# OT const_rename 128: packed / narrowed buses renamed (physical/die_plan/s81/inputs/const_pins_dropped.json)
VERSION 5.8 ;
BUSBITCHARS "[]" ;
DIVIDERCHAR "/" ;
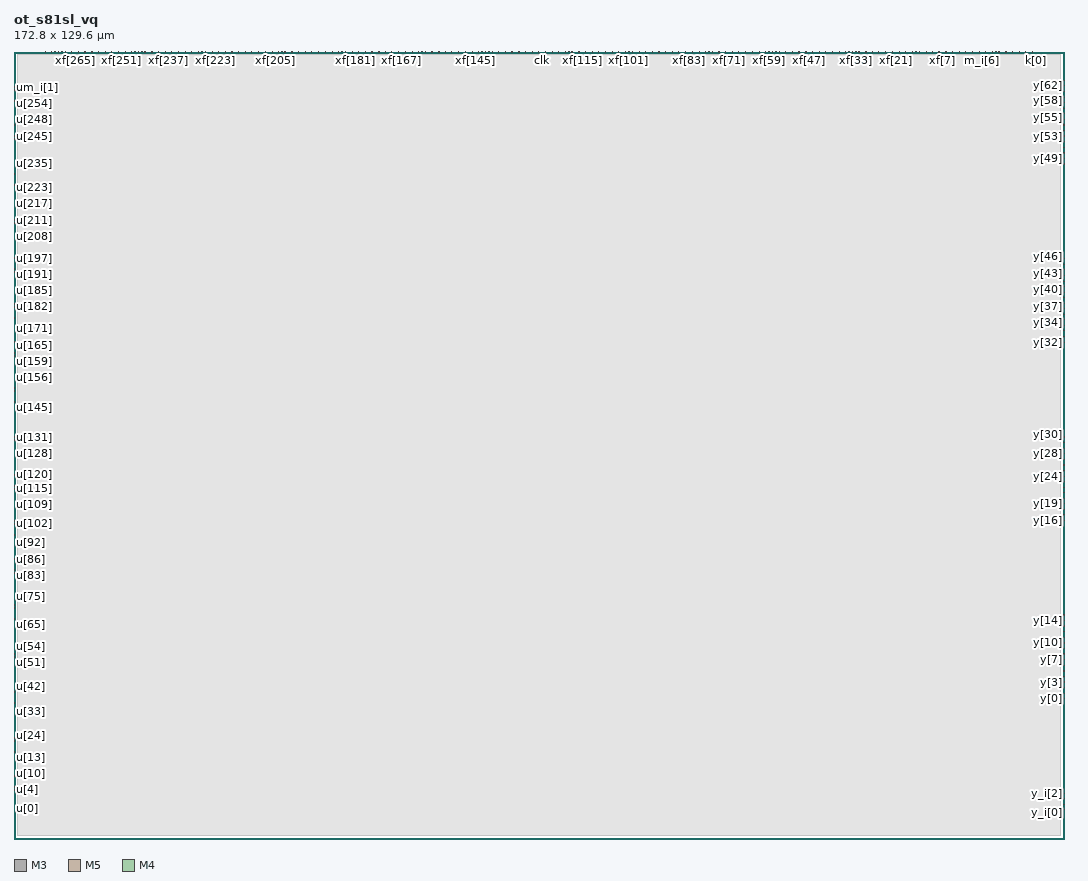
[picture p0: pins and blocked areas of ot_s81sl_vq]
MACRO ot_s81sl_vq
  CLASS BLOCK ;
  ORIGIN 0 0 ;
  FOREIGN ot_s81sl_vq 0 0 ;
  SIZE 172.800 BY 129.600 ;
  SYMMETRY X Y ;
  PIN clk
    DIRECTION INPUT ;
    USE SIGNAL ;
    PORT
      LAYER M3 ;
        RECT 86.9400 129.5620 86.9580 129.6000 ;
    END
  END clk
  PIN fault
    DIRECTION OUTPUT ;
    USE SIGNAL ;
    PORT
      LAYER M3 ;
        RECT 158.2920 129.5620 158.3100 129.6000 ;
    END
  END fault
  PIN k[0]
    DIRECTION INPUT ;
    USE SIGNAL ;
    PORT
      LAYER M3 ;
        RECT 168.1560 129.5620 168.1740 129.6000 ;
    END
  END k[0]
  PIN k[1]
    DIRECTION INPUT ;
    USE SIGNAL ;
    PORT
      LAYER M5 ;
        RECT 167.6640 129.5160 167.6880 129.6000 ;
    END
  END k[1]
  PIN k[2]
    DIRECTION INPUT ;
    USE SIGNAL ;
    PORT
      LAYER M3 ;
        RECT 167.0760 129.5620 167.0940 129.6000 ;
    END
  END k[2]
  PIN m_b
    DIRECTION INPUT ;
    USE SIGNAL ;
    PORT
      LAYER M5 ;
        RECT 163.2480 129.5160 163.2720 129.6000 ;
    END
  END m_b
  PIN m_i[0]
    DIRECTION INPUT ;
    USE SIGNAL ;
    PORT
      LAYER M3 ;
        RECT 162.6840 129.5620 162.7020 129.6000 ;
    END
  END m_i[0]
  PIN m_i[1]
    DIRECTION INPUT ;
    USE SIGNAL ;
    PORT
      LAYER M5 ;
        RECT 162.0960 129.5160 162.1200 129.6000 ;
    END
  END m_i[1]
  PIN m_i[2]
    DIRECTION INPUT ;
    USE SIGNAL ;
    PORT
      LAYER M3 ;
        RECT 161.6040 129.5620 161.6220 129.6000 ;
    END
  END m_i[2]
  PIN m_i[3]
    DIRECTION INPUT ;
    USE SIGNAL ;
    PORT
      LAYER M5 ;
        RECT 161.0400 129.5160 161.0640 129.6000 ;
    END
  END m_i[3]
  PIN m_i[4]
    DIRECTION INPUT ;
    USE SIGNAL ;
    PORT
      LAYER M3 ;
        RECT 160.5240 129.5620 160.5420 129.6000 ;
    END
  END m_i[4]
  PIN m_i[5]
    DIRECTION INPUT ;
    USE SIGNAL ;
    PORT
      LAYER M5 ;
        RECT 159.8880 129.5160 159.9120 129.6000 ;
    END
  END m_i[5]
  PIN m_i[6]
    DIRECTION INPUT ;
    USE SIGNAL ;
    PORT
      LAYER M3 ;
        RECT 159.3720 129.5620 159.3900 129.6000 ;
    END
  END m_i[6]
  PIN m_i[7]
    DIRECTION INPUT ;
    USE SIGNAL ;
    PORT
      LAYER M5 ;
        RECT 158.8320 129.5160 158.8560 129.6000 ;
    END
  END m_i[7]
  PIN m_q
    DIRECTION INPUT ;
    USE SIGNAL ;
    PORT
      LAYER M3 ;
        RECT 163.7640 129.5620 163.7820 129.6000 ;
    END
  END m_q
  PIN m_v
    DIRECTION INPUT ;
    USE SIGNAL ;
    PORT
      LAYER M5 ;
        RECT 164.3040 129.5160 164.3280 129.6000 ;
    END
  END m_v
  PIN rst_n
    DIRECTION INPUT ;
    USE SIGNAL ;
    PORT
      LAYER M5 ;
        RECT 86.3520 129.5160 86.3760 129.6000 ;
    END
  END rst_n
  PIN sid[0]
    DIRECTION INPUT ;
    USE SIGNAL ;
    PORT
      LAYER M5 ;
        RECT 166.5120 129.5160 166.5360 129.6000 ;
    END
  END sid[0]
  PIN sid[1]
    DIRECTION INPUT ;
    USE SIGNAL ;
    PORT
      LAYER M3 ;
        RECT 165.9960 129.5620 166.0140 129.6000 ;
    END
  END sid[1]
  PIN sid[2]
    DIRECTION INPUT ;
    USE SIGNAL ;
    PORT
      LAYER M5 ;
        RECT 165.4560 129.5160 165.4800 129.6000 ;
    END
  END sid[2]
  PIN sid[3]
    DIRECTION INPUT ;
    USE SIGNAL ;
    PORT
      LAYER M3 ;
        RECT 164.9160 129.5620 164.9340 129.6000 ;
    END
  END sid[3]
  PIN u[0]
    DIRECTION INPUT ;
    USE SIGNAL ;
    PORT
      LAYER M4 ;
        RECT 0.0000 6.3360 0.0840 6.3600 ;
    END
  END u[0]
  PIN u[100]
    DIRECTION INPUT ;
    USE SIGNAL ;
    PORT
      LAYER M4 ;
        RECT 0.0000 50.9760 0.0840 51.0000 ;
    END
  END u[100]
  PIN u[101]
    DIRECTION INPUT ;
    USE SIGNAL ;
    PORT
      LAYER M4 ;
        RECT 0.0000 51.3600 0.0840 51.3840 ;
    END
  END u[101]
  PIN u[102]
    DIRECTION INPUT ;
    USE SIGNAL ;
    PORT
      LAYER M4 ;
        RECT 0.0000 51.8400 0.0840 51.8640 ;
    END
  END u[102]
  PIN u[103]
    DIRECTION INPUT ;
    USE SIGNAL ;
    PORT
      LAYER M4 ;
        RECT 0.0000 52.3200 0.0840 52.3440 ;
    END
  END u[103]
  PIN u[104]
    DIRECTION INPUT ;
    USE SIGNAL ;
    PORT
      LAYER M4 ;
        RECT 0.0000 52.7040 0.0840 52.7280 ;
    END
  END u[104]
  PIN u[105]
    DIRECTION INPUT ;
    USE SIGNAL ;
    PORT
      LAYER M4 ;
        RECT 0.0000 53.1840 0.0840 53.2080 ;
    END
  END u[105]
  PIN u[106]
    DIRECTION INPUT ;
    USE SIGNAL ;
    PORT
      LAYER M4 ;
        RECT 0.0000 53.6640 0.0840 53.6880 ;
    END
  END u[106]
  PIN u[107]
    DIRECTION INPUT ;
    USE SIGNAL ;
    PORT
      LAYER M4 ;
        RECT 0.0000 54.0480 0.0840 54.0720 ;
    END
  END u[107]
  PIN u[108]
    DIRECTION INPUT ;
    USE SIGNAL ;
    PORT
      LAYER M4 ;
        RECT 0.0000 54.5280 0.0840 54.5520 ;
    END
  END u[108]
  PIN u[109]
    DIRECTION INPUT ;
    USE SIGNAL ;
    PORT
      LAYER M4 ;
        RECT 0.0000 55.0080 0.0840 55.0320 ;
    END
  END u[109]
  PIN u[10]
    DIRECTION INPUT ;
    USE SIGNAL ;
    PORT
      LAYER M4 ;
        RECT 0.0000 10.7520 0.0840 10.7760 ;
    END
  END u[10]
  PIN u[110]
    DIRECTION INPUT ;
    USE SIGNAL ;
    PORT
      LAYER M4 ;
        RECT 0.0000 55.3920 0.0840 55.4160 ;
    END
  END u[110]
  PIN u[111]
    DIRECTION INPUT ;
    USE SIGNAL ;
    PORT
      LAYER M4 ;
        RECT 0.0000 55.8720 0.0840 55.8960 ;
    END
  END u[111]
  PIN u[112]
    DIRECTION INPUT ;
    USE SIGNAL ;
    PORT
      LAYER M4 ;
        RECT 0.0000 56.3520 0.0840 56.3760 ;
    END
  END u[112]
  PIN u[113]
    DIRECTION INPUT ;
    USE SIGNAL ;
    PORT
      LAYER M4 ;
        RECT 0.0000 56.7360 0.0840 56.7600 ;
    END
  END u[113]
  PIN u[114]
    DIRECTION INPUT ;
    USE SIGNAL ;
    PORT
      LAYER M4 ;
        RECT 0.0000 57.2160 0.0840 57.2400 ;
    END
  END u[114]
  PIN u[115]
    DIRECTION INPUT ;
    USE SIGNAL ;
    PORT
      LAYER M4 ;
        RECT 0.0000 57.6000 0.0840 57.6240 ;
    END
  END u[115]
  PIN u[116]
    DIRECTION INPUT ;
    USE SIGNAL ;
    PORT
      LAYER M4 ;
        RECT 0.0000 58.0800 0.0840 58.1040 ;
    END
  END u[116]
  PIN u[117]
    DIRECTION INPUT ;
    USE SIGNAL ;
    PORT
      LAYER M4 ;
        RECT 0.0000 58.5600 0.0840 58.5840 ;
    END
  END u[117]
  PIN u[118]
    DIRECTION INPUT ;
    USE SIGNAL ;
    PORT
      LAYER M4 ;
        RECT 0.0000 58.9440 0.0840 58.9680 ;
    END
  END u[118]
  PIN u[119]
    DIRECTION INPUT ;
    USE SIGNAL ;
    PORT
      LAYER M4 ;
        RECT 0.0000 59.4240 0.0840 59.4480 ;
    END
  END u[119]
  PIN u[11]
    DIRECTION INPUT ;
    USE SIGNAL ;
    PORT
      LAYER M4 ;
        RECT 0.0000 11.2320 0.0840 11.2560 ;
    END
  END u[11]
  PIN u[120]
    DIRECTION INPUT ;
    USE SIGNAL ;
    PORT
      LAYER M4 ;
        RECT 0.0000 59.9040 0.0840 59.9280 ;
    END
  END u[120]
  PIN u[121]
    DIRECTION INPUT ;
    USE SIGNAL ;
    PORT
      LAYER M4 ;
        RECT 0.0000 60.2880 0.0840 60.3120 ;
    END
  END u[121]
  PIN u[122]
    DIRECTION INPUT ;
    USE SIGNAL ;
    PORT
      LAYER M4 ;
        RECT 0.0000 60.7680 0.0840 60.7920 ;
    END
  END u[122]
  PIN u[123]
    DIRECTION INPUT ;
    USE SIGNAL ;
    PORT
      LAYER M4 ;
        RECT 0.0000 61.2480 0.0840 61.2720 ;
    END
  END u[123]
  PIN u[124]
    DIRECTION INPUT ;
    USE SIGNAL ;
    PORT
      LAYER M4 ;
        RECT 0.0000 61.6320 0.0840 61.6560 ;
    END
  END u[124]
  PIN u[125]
    DIRECTION INPUT ;
    USE SIGNAL ;
    PORT
      LAYER M4 ;
        RECT 0.0000 62.1120 0.0840 62.1360 ;
    END
  END u[125]
  PIN u[126]
    DIRECTION INPUT ;
    USE SIGNAL ;
    PORT
      LAYER M4 ;
        RECT 0.0000 62.5920 0.0840 62.6160 ;
    END
  END u[126]
  PIN u[127]
    DIRECTION INPUT ;
    USE SIGNAL ;
    PORT
      LAYER M4 ;
        RECT 0.0000 62.9760 0.0840 63.0000 ;
    END
  END u[127]
  PIN u[128]
    DIRECTION INPUT ;
    USE SIGNAL ;
    PORT
      LAYER M4 ;
        RECT 0.0000 63.4560 0.0840 63.4800 ;
    END
  END u[128]
  PIN u[129]
    DIRECTION INPUT ;
    USE SIGNAL ;
    PORT
      LAYER M4 ;
        RECT 0.0000 63.9360 0.0840 63.9600 ;
    END
  END u[129]
  PIN u[12]
    DIRECTION INPUT ;
    USE SIGNAL ;
    PORT
      LAYER M4 ;
        RECT 0.0000 11.7120 0.0840 11.7360 ;
    END
  END u[12]
  PIN u[130]
    DIRECTION INPUT ;
    USE SIGNAL ;
    PORT
      LAYER M4 ;
        RECT 0.0000 64.3200 0.0840 64.3440 ;
    END
  END u[130]
  PIN u[131]
    DIRECTION INPUT ;
    USE SIGNAL ;
    PORT
      LAYER M4 ;
        RECT 0.0000 64.8000 0.0840 64.8240 ;
    END
  END u[131]
  PIN u[132]
    DIRECTION INPUT ;
    USE SIGNAL ;
    PORT
      LAYER M4 ;
        RECT 0.0000 65.2800 0.0840 65.3040 ;
    END
  END u[132]
  PIN u[133]
    DIRECTION INPUT ;
    USE SIGNAL ;
    PORT
      LAYER M4 ;
        RECT 0.0000 65.6640 0.0840 65.6880 ;
    END
  END u[133]
  PIN u[134]
    DIRECTION INPUT ;
    USE SIGNAL ;
    PORT
      LAYER M4 ;
        RECT 0.0000 66.1440 0.0840 66.1680 ;
    END
  END u[134]
  PIN u[135]
    DIRECTION INPUT ;
    USE SIGNAL ;
    PORT
      LAYER M4 ;
        RECT 0.0000 66.5280 0.0840 66.5520 ;
    END
  END u[135]
  PIN u[136]
    DIRECTION INPUT ;
    USE SIGNAL ;
    PORT
      LAYER M4 ;
        RECT 0.0000 67.0080 0.0840 67.0320 ;
    END
  END u[136]
  PIN u[137]
    DIRECTION INPUT ;
    USE SIGNAL ;
    PORT
      LAYER M4 ;
        RECT 0.0000 67.4880 0.0840 67.5120 ;
    END
  END u[137]
  PIN u[138]
    DIRECTION INPUT ;
    USE SIGNAL ;
    PORT
      LAYER M4 ;
        RECT 0.0000 67.8720 0.0840 67.8960 ;
    END
  END u[138]
  PIN u[139]
    DIRECTION INPUT ;
    USE SIGNAL ;
    PORT
      LAYER M4 ;
        RECT 0.0000 68.3520 0.0840 68.3760 ;
    END
  END u[139]
  PIN u[13]
    DIRECTION INPUT ;
    USE SIGNAL ;
    PORT
      LAYER M4 ;
        RECT 0.0000 12.0960 0.0840 12.1200 ;
    END
  END u[13]
  PIN u[140]
    DIRECTION INPUT ;
    USE SIGNAL ;
    PORT
      LAYER M4 ;
        RECT 0.0000 68.8320 0.0840 68.8560 ;
    END
  END u[140]
  PIN u[141]
    DIRECTION INPUT ;
    USE SIGNAL ;
    PORT
      LAYER M4 ;
        RECT 0.0000 69.2160 0.0840 69.2400 ;
    END
  END u[141]
  PIN u[142]
    DIRECTION INPUT ;
    USE SIGNAL ;
    PORT
      LAYER M4 ;
        RECT 0.0000 69.6960 0.0840 69.7200 ;
    END
  END u[142]
  PIN u[143]
    DIRECTION INPUT ;
    USE SIGNAL ;
    PORT
      LAYER M4 ;
        RECT 0.0000 70.1760 0.0840 70.2000 ;
    END
  END u[143]
  PIN u[144]
    DIRECTION INPUT ;
    USE SIGNAL ;
    PORT
      LAYER M4 ;
        RECT 0.0000 70.5600 0.0840 70.5840 ;
    END
  END u[144]
  PIN u[145]
    DIRECTION INPUT ;
    USE SIGNAL ;
    PORT
      LAYER M4 ;
        RECT 0.0000 71.0400 0.0840 71.0640 ;
    END
  END u[145]
  PIN u[146]
    DIRECTION INPUT ;
    USE SIGNAL ;
    PORT
      LAYER M4 ;
        RECT 0.0000 71.5200 0.0840 71.5440 ;
    END
  END u[146]
  PIN u[147]
    DIRECTION INPUT ;
    USE SIGNAL ;
    PORT
      LAYER M4 ;
        RECT 0.0000 71.9040 0.0840 71.9280 ;
    END
  END u[147]
  PIN u[148]
    DIRECTION INPUT ;
    USE SIGNAL ;
    PORT
      LAYER M4 ;
        RECT 0.0000 72.3840 0.0840 72.4080 ;
    END
  END u[148]
  PIN u[149]
    DIRECTION INPUT ;
    USE SIGNAL ;
    PORT
      LAYER M4 ;
        RECT 0.0000 72.8640 0.0840 72.8880 ;
    END
  END u[149]
  PIN u[14]
    DIRECTION INPUT ;
    USE SIGNAL ;
    PORT
      LAYER M4 ;
        RECT 0.0000 12.5760 0.0840 12.6000 ;
    END
  END u[14]
  PIN u[150]
    DIRECTION INPUT ;
    USE SIGNAL ;
    PORT
      LAYER M4 ;
        RECT 0.0000 73.2480 0.0840 73.2720 ;
    END
  END u[150]
  PIN u[151]
    DIRECTION INPUT ;
    USE SIGNAL ;
    PORT
      LAYER M4 ;
        RECT 0.0000 73.7280 0.0840 73.7520 ;
    END
  END u[151]
  PIN u[152]
    DIRECTION INPUT ;
    USE SIGNAL ;
    PORT
      LAYER M4 ;
        RECT 0.0000 74.2080 0.0840 74.2320 ;
    END
  END u[152]
  PIN u[153]
    DIRECTION INPUT ;
    USE SIGNAL ;
    PORT
      LAYER M4 ;
        RECT 0.0000 74.5920 0.0840 74.6160 ;
    END
  END u[153]
  PIN u[154]
    DIRECTION INPUT ;
    USE SIGNAL ;
    PORT
      LAYER M4 ;
        RECT 0.0000 75.0720 0.0840 75.0960 ;
    END
  END u[154]
  PIN u[155]
    DIRECTION INPUT ;
    USE SIGNAL ;
    PORT
      LAYER M4 ;
        RECT 0.0000 75.4560 0.0840 75.4800 ;
    END
  END u[155]
  PIN u[156]
    DIRECTION INPUT ;
    USE SIGNAL ;
    PORT
      LAYER M4 ;
        RECT 0.0000 75.9360 0.0840 75.9600 ;
    END
  END u[156]
  PIN u[157]
    DIRECTION INPUT ;
    USE SIGNAL ;
    PORT
      LAYER M4 ;
        RECT 0.0000 76.4160 0.0840 76.4400 ;
    END
  END u[157]
  PIN u[158]
    DIRECTION INPUT ;
    USE SIGNAL ;
    PORT
      LAYER M4 ;
        RECT 0.0000 76.8000 0.0840 76.8240 ;
    END
  END u[158]
  PIN u[159]
    DIRECTION INPUT ;
    USE SIGNAL ;
    PORT
      LAYER M4 ;
        RECT 0.0000 77.2800 0.0840 77.3040 ;
    END
  END u[159]
  PIN u[15]
    DIRECTION INPUT ;
    USE SIGNAL ;
    PORT
      LAYER M4 ;
        RECT 0.0000 13.0560 0.0840 13.0800 ;
    END
  END u[15]
  PIN u[160]
    DIRECTION INPUT ;
    USE SIGNAL ;
    PORT
      LAYER M4 ;
        RECT 0.0000 77.7600 0.0840 77.7840 ;
    END
  END u[160]
  PIN u[161]
    DIRECTION INPUT ;
    USE SIGNAL ;
    PORT
      LAYER M4 ;
        RECT 0.0000 78.1440 0.0840 78.1680 ;
    END
  END u[161]
  PIN u[162]
    DIRECTION INPUT ;
    USE SIGNAL ;
    PORT
      LAYER M4 ;
        RECT 0.0000 78.6240 0.0840 78.6480 ;
    END
  END u[162]
  PIN u[163]
    DIRECTION INPUT ;
    USE SIGNAL ;
    PORT
      LAYER M4 ;
        RECT 0.0000 79.1040 0.0840 79.1280 ;
    END
  END u[163]
  PIN u[164]
    DIRECTION INPUT ;
    USE SIGNAL ;
    PORT
      LAYER M4 ;
        RECT 0.0000 79.4880 0.0840 79.5120 ;
    END
  END u[164]
  PIN u[165]
    DIRECTION INPUT ;
    USE SIGNAL ;
    PORT
      LAYER M4 ;
        RECT 0.0000 79.9680 0.0840 79.9920 ;
    END
  END u[165]
  PIN u[166]
    DIRECTION INPUT ;
    USE SIGNAL ;
    PORT
      LAYER M4 ;
        RECT 0.0000 80.4480 0.0840 80.4720 ;
    END
  END u[166]
  PIN u[167]
    DIRECTION INPUT ;
    USE SIGNAL ;
    PORT
      LAYER M4 ;
        RECT 0.0000 80.8320 0.0840 80.8560 ;
    END
  END u[167]
  PIN u[168]
    DIRECTION INPUT ;
    USE SIGNAL ;
    PORT
      LAYER M4 ;
        RECT 0.0000 81.3120 0.0840 81.3360 ;
    END
  END u[168]
  PIN u[169]
    DIRECTION INPUT ;
    USE SIGNAL ;
    PORT
      LAYER M4 ;
        RECT 0.0000 81.7920 0.0840 81.8160 ;
    END
  END u[169]
  PIN u[16]
    DIRECTION INPUT ;
    USE SIGNAL ;
    PORT
      LAYER M4 ;
        RECT 0.0000 13.4400 0.0840 13.4640 ;
    END
  END u[16]
  PIN u[170]
    DIRECTION INPUT ;
    USE SIGNAL ;
    PORT
      LAYER M4 ;
        RECT 0.0000 82.1760 0.0840 82.2000 ;
    END
  END u[170]
  PIN u[171]
    DIRECTION INPUT ;
    USE SIGNAL ;
    PORT
      LAYER M4 ;
        RECT 0.0000 82.6560 0.0840 82.6800 ;
    END
  END u[171]
  PIN u[172]
    DIRECTION INPUT ;
    USE SIGNAL ;
    PORT
      LAYER M4 ;
        RECT 0.0000 83.1360 0.0840 83.1600 ;
    END
  END u[172]
  PIN u[173]
    DIRECTION INPUT ;
    USE SIGNAL ;
    PORT
      LAYER M4 ;
        RECT 0.0000 83.5200 0.0840 83.5440 ;
    END
  END u[173]
  PIN u[174]
    DIRECTION INPUT ;
    USE SIGNAL ;
    PORT
      LAYER M4 ;
        RECT 0.0000 84.0000 0.0840 84.0240 ;
    END
  END u[174]
  PIN u[175]
    DIRECTION INPUT ;
    USE SIGNAL ;
    PORT
      LAYER M4 ;
        RECT 0.0000 84.3840 0.0840 84.4080 ;
    END
  END u[175]
  PIN u[176]
    DIRECTION INPUT ;
    USE SIGNAL ;
    PORT
      LAYER M4 ;
        RECT 0.0000 84.8640 0.0840 84.8880 ;
    END
  END u[176]
  PIN u[177]
    DIRECTION INPUT ;
    USE SIGNAL ;
    PORT
      LAYER M4 ;
        RECT 0.0000 85.3440 0.0840 85.3680 ;
    END
  END u[177]
  PIN u[178]
    DIRECTION INPUT ;
    USE SIGNAL ;
    PORT
      LAYER M4 ;
        RECT 0.0000 85.7280 0.0840 85.7520 ;
    END
  END u[178]
  PIN u[179]
    DIRECTION INPUT ;
    USE SIGNAL ;
    PORT
      LAYER M4 ;
        RECT 0.0000 86.2080 0.0840 86.2320 ;
    END
  END u[179]
  PIN u[17]
    DIRECTION INPUT ;
    USE SIGNAL ;
    PORT
      LAYER M4 ;
        RECT 0.0000 13.9200 0.0840 13.9440 ;
    END
  END u[17]
  PIN u[180]
    DIRECTION INPUT ;
    USE SIGNAL ;
    PORT
      LAYER M4 ;
        RECT 0.0000 86.6880 0.0840 86.7120 ;
    END
  END u[180]
  PIN u[181]
    DIRECTION INPUT ;
    USE SIGNAL ;
    PORT
      LAYER M4 ;
        RECT 0.0000 87.0720 0.0840 87.0960 ;
    END
  END u[181]
  PIN u[182]
    DIRECTION INPUT ;
    USE SIGNAL ;
    PORT
      LAYER M4 ;
        RECT 0.0000 87.5520 0.0840 87.5760 ;
    END
  END u[182]
  PIN u[183]
    DIRECTION INPUT ;
    USE SIGNAL ;
    PORT
      LAYER M4 ;
        RECT 0.0000 88.0320 0.0840 88.0560 ;
    END
  END u[183]
  PIN u[184]
    DIRECTION INPUT ;
    USE SIGNAL ;
    PORT
      LAYER M4 ;
        RECT 0.0000 88.4160 0.0840 88.4400 ;
    END
  END u[184]
  PIN u[185]
    DIRECTION INPUT ;
    USE SIGNAL ;
    PORT
      LAYER M4 ;
        RECT 0.0000 88.8960 0.0840 88.9200 ;
    END
  END u[185]
  PIN u[186]
    DIRECTION INPUT ;
    USE SIGNAL ;
    PORT
      LAYER M4 ;
        RECT 0.0000 89.3760 0.0840 89.4000 ;
    END
  END u[186]
  PIN u[187]
    DIRECTION INPUT ;
    USE SIGNAL ;
    PORT
      LAYER M4 ;
        RECT 0.0000 89.7600 0.0840 89.7840 ;
    END
  END u[187]
  PIN u[188]
    DIRECTION INPUT ;
    USE SIGNAL ;
    PORT
      LAYER M4 ;
        RECT 0.0000 90.2400 0.0840 90.2640 ;
    END
  END u[188]
  PIN u[189]
    DIRECTION INPUT ;
    USE SIGNAL ;
    PORT
      LAYER M4 ;
        RECT 0.0000 90.7200 0.0840 90.7440 ;
    END
  END u[189]
  PIN u[18]
    DIRECTION INPUT ;
    USE SIGNAL ;
    PORT
      LAYER M4 ;
        RECT 0.0000 14.3040 0.0840 14.3280 ;
    END
  END u[18]
  PIN u[190]
    DIRECTION INPUT ;
    USE SIGNAL ;
    PORT
      LAYER M4 ;
        RECT 0.0000 91.1040 0.0840 91.1280 ;
    END
  END u[190]
  PIN u[191]
    DIRECTION INPUT ;
    USE SIGNAL ;
    PORT
      LAYER M4 ;
        RECT 0.0000 91.5840 0.0840 91.6080 ;
    END
  END u[191]
  PIN u[192]
    DIRECTION INPUT ;
    USE SIGNAL ;
    PORT
      LAYER M4 ;
        RECT 0.0000 91.9680 0.0840 91.9920 ;
    END
  END u[192]
  PIN u[193]
    DIRECTION INPUT ;
    USE SIGNAL ;
    PORT
      LAYER M4 ;
        RECT 0.0000 92.4480 0.0840 92.4720 ;
    END
  END u[193]
  PIN u[194]
    DIRECTION INPUT ;
    USE SIGNAL ;
    PORT
      LAYER M4 ;
        RECT 0.0000 92.9280 0.0840 92.9520 ;
    END
  END u[194]
  PIN u[195]
    DIRECTION INPUT ;
    USE SIGNAL ;
    PORT
      LAYER M4 ;
        RECT 0.0000 93.3120 0.0840 93.3360 ;
    END
  END u[195]
  PIN u[196]
    DIRECTION INPUT ;
    USE SIGNAL ;
    PORT
      LAYER M4 ;
        RECT 0.0000 93.7920 0.0840 93.8160 ;
    END
  END u[196]
  PIN u[197]
    DIRECTION INPUT ;
    USE SIGNAL ;
    PORT
      LAYER M4 ;
        RECT 0.0000 94.2720 0.0840 94.2960 ;
    END
  END u[197]
  PIN u[198]
    DIRECTION INPUT ;
    USE SIGNAL ;
    PORT
      LAYER M4 ;
        RECT 0.0000 94.6560 0.0840 94.6800 ;
    END
  END u[198]
  PIN u[199]
    DIRECTION INPUT ;
    USE SIGNAL ;
    PORT
      LAYER M4 ;
        RECT 0.0000 95.1360 0.0840 95.1600 ;
    END
  END u[199]
  PIN u[19]
    DIRECTION INPUT ;
    USE SIGNAL ;
    PORT
      LAYER M4 ;
        RECT 0.0000 14.7840 0.0840 14.8080 ;
    END
  END u[19]
  PIN u[1]
    DIRECTION INPUT ;
    USE SIGNAL ;
    PORT
      LAYER M4 ;
        RECT 0.0000 6.7200 0.0840 6.7440 ;
    END
  END u[1]
  PIN u[200]
    DIRECTION INPUT ;
    USE SIGNAL ;
    PORT
      LAYER M4 ;
        RECT 0.0000 95.6160 0.0840 95.6400 ;
    END
  END u[200]
  PIN u[201]
    DIRECTION INPUT ;
    USE SIGNAL ;
    PORT
      LAYER M4 ;
        RECT 0.0000 96.0000 0.0840 96.0240 ;
    END
  END u[201]
  PIN u[202]
    DIRECTION INPUT ;
    USE SIGNAL ;
    PORT
      LAYER M4 ;
        RECT 0.0000 96.4800 0.0840 96.5040 ;
    END
  END u[202]
  PIN u[203]
    DIRECTION INPUT ;
    USE SIGNAL ;
    PORT
      LAYER M4 ;
        RECT 0.0000 96.9600 0.0840 96.9840 ;
    END
  END u[203]
  PIN u[204]
    DIRECTION INPUT ;
    USE SIGNAL ;
    PORT
      LAYER M4 ;
        RECT 0.0000 97.3440 0.0840 97.3680 ;
    END
  END u[204]
  PIN u[205]
    DIRECTION INPUT ;
    USE SIGNAL ;
    PORT
      LAYER M4 ;
        RECT 0.0000 97.8240 0.0840 97.8480 ;
    END
  END u[205]
  PIN u[206]
    DIRECTION INPUT ;
    USE SIGNAL ;
    PORT
      LAYER M4 ;
        RECT 0.0000 98.3040 0.0840 98.3280 ;
    END
  END u[206]
  PIN u[207]
    DIRECTION INPUT ;
    USE SIGNAL ;
    PORT
      LAYER M4 ;
        RECT 0.0000 98.6880 0.0840 98.7120 ;
    END
  END u[207]
  PIN u[208]
    DIRECTION INPUT ;
    USE SIGNAL ;
    PORT
      LAYER M4 ;
        RECT 0.0000 99.1680 0.0840 99.1920 ;
    END
  END u[208]
  PIN u[209]
    DIRECTION INPUT ;
    USE SIGNAL ;
    PORT
      LAYER M4 ;
        RECT 0.0000 99.6480 0.0840 99.6720 ;
    END
  END u[209]
  PIN u[20]
    DIRECTION INPUT ;
    USE SIGNAL ;
    PORT
      LAYER M4 ;
        RECT 0.0000 15.2640 0.0840 15.2880 ;
    END
  END u[20]
  PIN u[210]
    DIRECTION INPUT ;
    USE SIGNAL ;
    PORT
      LAYER M4 ;
        RECT 0.0000 100.0320 0.0840 100.0560 ;
    END
  END u[210]
  PIN u[211]
    DIRECTION INPUT ;
    USE SIGNAL ;
    PORT
      LAYER M4 ;
        RECT 0.0000 100.5120 0.0840 100.5360 ;
    END
  END u[211]
  PIN u[212]
    DIRECTION INPUT ;
    USE SIGNAL ;
    PORT
      LAYER M4 ;
        RECT 0.0000 100.8960 0.0840 100.9200 ;
    END
  END u[212]
  PIN u[213]
    DIRECTION INPUT ;
    USE SIGNAL ;
    PORT
      LAYER M4 ;
        RECT 0.0000 101.3760 0.0840 101.4000 ;
    END
  END u[213]
  PIN u[214]
    DIRECTION INPUT ;
    USE SIGNAL ;
    PORT
      LAYER M4 ;
        RECT 0.0000 101.8560 0.0840 101.8800 ;
    END
  END u[214]
  PIN u[215]
    DIRECTION INPUT ;
    USE SIGNAL ;
    PORT
      LAYER M4 ;
        RECT 0.0000 102.2400 0.0840 102.2640 ;
    END
  END u[215]
  PIN u[216]
    DIRECTION INPUT ;
    USE SIGNAL ;
    PORT
      LAYER M4 ;
        RECT 0.0000 102.7200 0.0840 102.7440 ;
    END
  END u[216]
  PIN u[217]
    DIRECTION INPUT ;
    USE SIGNAL ;
    PORT
      LAYER M4 ;
        RECT 0.0000 103.2000 0.0840 103.2240 ;
    END
  END u[217]
  PIN u[218]
    DIRECTION INPUT ;
    USE SIGNAL ;
    PORT
      LAYER M4 ;
        RECT 0.0000 103.5840 0.0840 103.6080 ;
    END
  END u[218]
  PIN u[219]
    DIRECTION INPUT ;
    USE SIGNAL ;
    PORT
      LAYER M4 ;
        RECT 0.0000 104.0640 0.0840 104.0880 ;
    END
  END u[219]
  PIN u[21]
    DIRECTION INPUT ;
    USE SIGNAL ;
    PORT
      LAYER M4 ;
        RECT 0.0000 15.6480 0.0840 15.6720 ;
    END
  END u[21]
  PIN u[220]
    DIRECTION INPUT ;
    USE SIGNAL ;
    PORT
      LAYER M4 ;
        RECT 0.0000 104.5440 0.0840 104.5680 ;
    END
  END u[220]
  PIN u[221]
    DIRECTION INPUT ;
    USE SIGNAL ;
    PORT
      LAYER M4 ;
        RECT 0.0000 104.9280 0.0840 104.9520 ;
    END
  END u[221]
  PIN u[222]
    DIRECTION INPUT ;
    USE SIGNAL ;
    PORT
      LAYER M4 ;
        RECT 0.0000 105.4080 0.0840 105.4320 ;
    END
  END u[222]
  PIN u[223]
    DIRECTION INPUT ;
    USE SIGNAL ;
    PORT
      LAYER M4 ;
        RECT 0.0000 105.8880 0.0840 105.9120 ;
    END
  END u[223]
  PIN u[224]
    DIRECTION INPUT ;
    USE SIGNAL ;
    PORT
      LAYER M4 ;
        RECT 0.0000 106.2720 0.0840 106.2960 ;
    END
  END u[224]
  PIN u[225]
    DIRECTION INPUT ;
    USE SIGNAL ;
    PORT
      LAYER M4 ;
        RECT 0.0000 106.7520 0.0840 106.7760 ;
    END
  END u[225]
  PIN u[226]
    DIRECTION INPUT ;
    USE SIGNAL ;
    PORT
      LAYER M4 ;
        RECT 0.0000 107.2320 0.0840 107.2560 ;
    END
  END u[226]
  PIN u[227]
    DIRECTION INPUT ;
    USE SIGNAL ;
    PORT
      LAYER M4 ;
        RECT 0.0000 107.6160 0.0840 107.6400 ;
    END
  END u[227]
  PIN u[228]
    DIRECTION INPUT ;
    USE SIGNAL ;
    PORT
      LAYER M4 ;
        RECT 0.0000 108.0960 0.0840 108.1200 ;
    END
  END u[228]
  PIN u[229]
    DIRECTION INPUT ;
    USE SIGNAL ;
    PORT
      LAYER M4 ;
        RECT 0.0000 108.5760 0.0840 108.6000 ;
    END
  END u[229]
  PIN u[22]
    DIRECTION INPUT ;
    USE SIGNAL ;
    PORT
      LAYER M4 ;
        RECT 0.0000 16.1280 0.0840 16.1520 ;
    END
  END u[22]
  PIN u[230]
    DIRECTION INPUT ;
    USE SIGNAL ;
    PORT
      LAYER M4 ;
        RECT 0.0000 108.9600 0.0840 108.9840 ;
    END
  END u[230]
  PIN u[231]
    DIRECTION INPUT ;
    USE SIGNAL ;
    PORT
      LAYER M4 ;
        RECT 0.0000 109.4400 0.0840 109.4640 ;
    END
  END u[231]
  PIN u[232]
    DIRECTION INPUT ;
    USE SIGNAL ;
    PORT
      LAYER M4 ;
        RECT 0.0000 109.8240 0.0840 109.8480 ;
    END
  END u[232]
  PIN u[233]
    DIRECTION INPUT ;
    USE SIGNAL ;
    PORT
      LAYER M4 ;
        RECT 0.0000 110.3040 0.0840 110.3280 ;
    END
  END u[233]
  PIN u[234]
    DIRECTION INPUT ;
    USE SIGNAL ;
    PORT
      LAYER M4 ;
        RECT 0.0000 110.7840 0.0840 110.8080 ;
    END
  END u[234]
  PIN u[235]
    DIRECTION INPUT ;
    USE SIGNAL ;
    PORT
      LAYER M4 ;
        RECT 0.0000 111.1680 0.0840 111.1920 ;
    END
  END u[235]
  PIN u[236]
    DIRECTION INPUT ;
    USE SIGNAL ;
    PORT
      LAYER M4 ;
        RECT 0.0000 111.6480 0.0840 111.6720 ;
    END
  END u[236]
  PIN u[237]
    DIRECTION INPUT ;
    USE SIGNAL ;
    PORT
      LAYER M4 ;
        RECT 0.0000 112.1280 0.0840 112.1520 ;
    END
  END u[237]
  PIN u[238]
    DIRECTION INPUT ;
    USE SIGNAL ;
    PORT
      LAYER M4 ;
        RECT 0.0000 112.5120 0.0840 112.5360 ;
    END
  END u[238]
  PIN u[239]
    DIRECTION INPUT ;
    USE SIGNAL ;
    PORT
      LAYER M4 ;
        RECT 0.0000 112.9920 0.0840 113.0160 ;
    END
  END u[239]
  PIN u[23]
    DIRECTION INPUT ;
    USE SIGNAL ;
    PORT
      LAYER M4 ;
        RECT 0.0000 16.6080 0.0840 16.6320 ;
    END
  END u[23]
  PIN u[240]
    DIRECTION INPUT ;
    USE SIGNAL ;
    PORT
      LAYER M4 ;
        RECT 0.0000 113.4720 0.0840 113.4960 ;
    END
  END u[240]
  PIN u[241]
    DIRECTION INPUT ;
    USE SIGNAL ;
    PORT
      LAYER M4 ;
        RECT 0.0000 113.8560 0.0840 113.8800 ;
    END
  END u[241]
  PIN u[242]
    DIRECTION INPUT ;
    USE SIGNAL ;
    PORT
      LAYER M4 ;
        RECT 0.0000 114.3360 0.0840 114.3600 ;
    END
  END u[242]
  PIN u[243]
    DIRECTION INPUT ;
    USE SIGNAL ;
    PORT
      LAYER M4 ;
        RECT 0.0000 114.8160 0.0840 114.8400 ;
    END
  END u[243]
  PIN u[244]
    DIRECTION INPUT ;
    USE SIGNAL ;
    PORT
      LAYER M4 ;
        RECT 0.0000 115.2000 0.0840 115.2240 ;
    END
  END u[244]
  PIN u[245]
    DIRECTION INPUT ;
    USE SIGNAL ;
    PORT
      LAYER M4 ;
        RECT 0.0000 115.6800 0.0840 115.7040 ;
    END
  END u[245]
  PIN u[246]
    DIRECTION INPUT ;
    USE SIGNAL ;
    PORT
      LAYER M4 ;
        RECT 0.0000 116.1600 0.0840 116.1840 ;
    END
  END u[246]
  PIN u[247]
    DIRECTION INPUT ;
    USE SIGNAL ;
    PORT
      LAYER M4 ;
        RECT 0.0000 116.5440 0.0840 116.5680 ;
    END
  END u[247]
  PIN u[248]
    DIRECTION INPUT ;
    USE SIGNAL ;
    PORT
      LAYER M4 ;
        RECT 0.0000 117.0240 0.0840 117.0480 ;
    END
  END u[248]
  PIN u[249]
    DIRECTION INPUT ;
    USE SIGNAL ;
    PORT
      LAYER M4 ;
        RECT 0.0000 117.5040 0.0840 117.5280 ;
    END
  END u[249]
  PIN u[24]
    DIRECTION INPUT ;
    USE SIGNAL ;
    PORT
      LAYER M4 ;
        RECT 0.0000 16.9920 0.0840 17.0160 ;
    END
  END u[24]
  PIN u[250]
    DIRECTION INPUT ;
    USE SIGNAL ;
    PORT
      LAYER M4 ;
        RECT 0.0000 117.8880 0.0840 117.9120 ;
    END
  END u[250]
  PIN u[251]
    DIRECTION INPUT ;
    USE SIGNAL ;
    PORT
      LAYER M4 ;
        RECT 0.0000 118.3680 0.0840 118.3920 ;
    END
  END u[251]
  PIN u[252]
    DIRECTION INPUT ;
    USE SIGNAL ;
    PORT
      LAYER M4 ;
        RECT 0.0000 118.7520 0.0840 118.7760 ;
    END
  END u[252]
  PIN u[253]
    DIRECTION INPUT ;
    USE SIGNAL ;
    PORT
      LAYER M4 ;
        RECT 0.0000 119.2320 0.0840 119.2560 ;
    END
  END u[253]
  PIN u[254]
    DIRECTION INPUT ;
    USE SIGNAL ;
    PORT
      LAYER M4 ;
        RECT 0.0000 119.7120 0.0840 119.7360 ;
    END
  END u[254]
  PIN u[255]
    DIRECTION INPUT ;
    USE SIGNAL ;
    PORT
      LAYER M4 ;
        RECT 0.0000 120.0960 0.0840 120.1200 ;
    END
  END u[255]
  PIN u[25]
    DIRECTION INPUT ;
    USE SIGNAL ;
    PORT
      LAYER M4 ;
        RECT 0.0000 17.4720 0.0840 17.4960 ;
    END
  END u[25]
  PIN u[26]
    DIRECTION INPUT ;
    USE SIGNAL ;
    PORT
      LAYER M4 ;
        RECT 0.0000 17.9520 0.0840 17.9760 ;
    END
  END u[26]
  PIN u[27]
    DIRECTION INPUT ;
    USE SIGNAL ;
    PORT
      LAYER M4 ;
        RECT 0.0000 18.3360 0.0840 18.3600 ;
    END
  END u[27]
  PIN u[28]
    DIRECTION INPUT ;
    USE SIGNAL ;
    PORT
      LAYER M4 ;
        RECT 0.0000 18.8160 0.0840 18.8400 ;
    END
  END u[28]
  PIN u[29]
    DIRECTION INPUT ;
    USE SIGNAL ;
    PORT
      LAYER M4 ;
        RECT 0.0000 19.2960 0.0840 19.3200 ;
    END
  END u[29]
  PIN u[2]
    DIRECTION INPUT ;
    USE SIGNAL ;
    PORT
      LAYER M4 ;
        RECT 0.0000 7.2000 0.0840 7.2240 ;
    END
  END u[2]
  PIN u[30]
    DIRECTION INPUT ;
    USE SIGNAL ;
    PORT
      LAYER M4 ;
        RECT 0.0000 19.6800 0.0840 19.7040 ;
    END
  END u[30]
  PIN u[31]
    DIRECTION INPUT ;
    USE SIGNAL ;
    PORT
      LAYER M4 ;
        RECT 0.0000 20.1600 0.0840 20.1840 ;
    END
  END u[31]
  PIN u[32]
    DIRECTION INPUT ;
    USE SIGNAL ;
    PORT
      LAYER M4 ;
        RECT 0.0000 20.6400 0.0840 20.6640 ;
    END
  END u[32]
  PIN u[33]
    DIRECTION INPUT ;
    USE SIGNAL ;
    PORT
      LAYER M4 ;
        RECT 0.0000 21.0240 0.0840 21.0480 ;
    END
  END u[33]
  PIN u[34]
    DIRECTION INPUT ;
    USE SIGNAL ;
    PORT
      LAYER M4 ;
        RECT 0.0000 21.5040 0.0840 21.5280 ;
    END
  END u[34]
  PIN u[35]
    DIRECTION INPUT ;
    USE SIGNAL ;
    PORT
      LAYER M4 ;
        RECT 0.0000 21.9840 0.0840 22.0080 ;
    END
  END u[35]
  PIN u[36]
    DIRECTION INPUT ;
    USE SIGNAL ;
    PORT
      LAYER M4 ;
        RECT 0.0000 22.3680 0.0840 22.3920 ;
    END
  END u[36]
  PIN u[37]
    DIRECTION INPUT ;
    USE SIGNAL ;
    PORT
      LAYER M4 ;
        RECT 0.0000 22.8480 0.0840 22.8720 ;
    END
  END u[37]
  PIN u[38]
    DIRECTION INPUT ;
    USE SIGNAL ;
    PORT
      LAYER M4 ;
        RECT 0.0000 23.2320 0.0840 23.2560 ;
    END
  END u[38]
  PIN u[39]
    DIRECTION INPUT ;
    USE SIGNAL ;
    PORT
      LAYER M4 ;
        RECT 0.0000 23.7120 0.0840 23.7360 ;
    END
  END u[39]
  PIN u[3]
    DIRECTION INPUT ;
    USE SIGNAL ;
    PORT
      LAYER M4 ;
        RECT 0.0000 7.6800 0.0840 7.7040 ;
    END
  END u[3]
  PIN u[40]
    DIRECTION INPUT ;
    USE SIGNAL ;
    PORT
      LAYER M4 ;
        RECT 0.0000 24.1920 0.0840 24.2160 ;
    END
  END u[40]
  PIN u[41]
    DIRECTION INPUT ;
    USE SIGNAL ;
    PORT
      LAYER M4 ;
        RECT 0.0000 24.5760 0.0840 24.6000 ;
    END
  END u[41]
  PIN u[42]
    DIRECTION INPUT ;
    USE SIGNAL ;
    PORT
      LAYER M4 ;
        RECT 0.0000 25.0560 0.0840 25.0800 ;
    END
  END u[42]
  PIN u[43]
    DIRECTION INPUT ;
    USE SIGNAL ;
    PORT
      LAYER M4 ;
        RECT 0.0000 25.5360 0.0840 25.5600 ;
    END
  END u[43]
  PIN u[44]
    DIRECTION INPUT ;
    USE SIGNAL ;
    PORT
      LAYER M4 ;
        RECT 0.0000 25.9200 0.0840 25.9440 ;
    END
  END u[44]
  PIN u[45]
    DIRECTION INPUT ;
    USE SIGNAL ;
    PORT
      LAYER M4 ;
        RECT 0.0000 26.4000 0.0840 26.4240 ;
    END
  END u[45]
  PIN u[46]
    DIRECTION INPUT ;
    USE SIGNAL ;
    PORT
      LAYER M4 ;
        RECT 0.0000 26.8800 0.0840 26.9040 ;
    END
  END u[46]
  PIN u[47]
    DIRECTION INPUT ;
    USE SIGNAL ;
    PORT
      LAYER M4 ;
        RECT 0.0000 27.2640 0.0840 27.2880 ;
    END
  END u[47]
  PIN u[48]
    DIRECTION INPUT ;
    USE SIGNAL ;
    PORT
      LAYER M4 ;
        RECT 0.0000 27.7440 0.0840 27.7680 ;
    END
  END u[48]
  PIN u[49]
    DIRECTION INPUT ;
    USE SIGNAL ;
    PORT
      LAYER M4 ;
        RECT 0.0000 28.2240 0.0840 28.2480 ;
    END
  END u[49]
  PIN u[4]
    DIRECTION INPUT ;
    USE SIGNAL ;
    PORT
      LAYER M4 ;
        RECT 0.0000 8.0640 0.0840 8.0880 ;
    END
  END u[4]
  PIN u[50]
    DIRECTION INPUT ;
    USE SIGNAL ;
    PORT
      LAYER M4 ;
        RECT 0.0000 28.6080 0.0840 28.6320 ;
    END
  END u[50]
  PIN u[51]
    DIRECTION INPUT ;
    USE SIGNAL ;
    PORT
      LAYER M4 ;
        RECT 0.0000 29.0880 0.0840 29.1120 ;
    END
  END u[51]
  PIN u[52]
    DIRECTION INPUT ;
    USE SIGNAL ;
    PORT
      LAYER M4 ;
        RECT 0.0000 29.5680 0.0840 29.5920 ;
    END
  END u[52]
  PIN u[53]
    DIRECTION INPUT ;
    USE SIGNAL ;
    PORT
      LAYER M4 ;
        RECT 0.0000 29.9520 0.0840 29.9760 ;
    END
  END u[53]
  PIN u[54]
    DIRECTION INPUT ;
    USE SIGNAL ;
    PORT
      LAYER M4 ;
        RECT 0.0000 30.4320 0.0840 30.4560 ;
    END
  END u[54]
  PIN u[55]
    DIRECTION INPUT ;
    USE SIGNAL ;
    PORT
      LAYER M4 ;
        RECT 0.0000 30.9120 0.0840 30.9360 ;
    END
  END u[55]
  PIN u[56]
    DIRECTION INPUT ;
    USE SIGNAL ;
    PORT
      LAYER M4 ;
        RECT 0.0000 31.2960 0.0840 31.3200 ;
    END
  END u[56]
  PIN u[57]
    DIRECTION INPUT ;
    USE SIGNAL ;
    PORT
      LAYER M4 ;
        RECT 0.0000 31.7760 0.0840 31.8000 ;
    END
  END u[57]
  PIN u[58]
    DIRECTION INPUT ;
    USE SIGNAL ;
    PORT
      LAYER M4 ;
        RECT 0.0000 32.1600 0.0840 32.1840 ;
    END
  END u[58]
  PIN u[59]
    DIRECTION INPUT ;
    USE SIGNAL ;
    PORT
      LAYER M4 ;
        RECT 0.0000 32.6400 0.0840 32.6640 ;
    END
  END u[59]
  PIN u[5]
    DIRECTION INPUT ;
    USE SIGNAL ;
    PORT
      LAYER M4 ;
        RECT 0.0000 8.5440 0.0840 8.5680 ;
    END
  END u[5]
  PIN u[60]
    DIRECTION INPUT ;
    USE SIGNAL ;
    PORT
      LAYER M4 ;
        RECT 0.0000 33.1200 0.0840 33.1440 ;
    END
  END u[60]
  PIN u[61]
    DIRECTION INPUT ;
    USE SIGNAL ;
    PORT
      LAYER M4 ;
        RECT 0.0000 33.5040 0.0840 33.5280 ;
    END
  END u[61]
  PIN u[62]
    DIRECTION INPUT ;
    USE SIGNAL ;
    PORT
      LAYER M4 ;
        RECT 0.0000 33.9840 0.0840 34.0080 ;
    END
  END u[62]
  PIN u[63]
    DIRECTION INPUT ;
    USE SIGNAL ;
    PORT
      LAYER M4 ;
        RECT 0.0000 34.4640 0.0840 34.4880 ;
    END
  END u[63]
  PIN u[64]
    DIRECTION INPUT ;
    USE SIGNAL ;
    PORT
      LAYER M4 ;
        RECT 0.0000 34.8480 0.0840 34.8720 ;
    END
  END u[64]
  PIN u[65]
    DIRECTION INPUT ;
    USE SIGNAL ;
    PORT
      LAYER M4 ;
        RECT 0.0000 35.3280 0.0840 35.3520 ;
    END
  END u[65]
  PIN u[66]
    DIRECTION INPUT ;
    USE SIGNAL ;
    PORT
      LAYER M4 ;
        RECT 0.0000 35.8080 0.0840 35.8320 ;
    END
  END u[66]
  PIN u[67]
    DIRECTION INPUT ;
    USE SIGNAL ;
    PORT
      LAYER M4 ;
        RECT 0.0000 36.1920 0.0840 36.2160 ;
    END
  END u[67]
  PIN u[68]
    DIRECTION INPUT ;
    USE SIGNAL ;
    PORT
      LAYER M4 ;
        RECT 0.0000 36.6720 0.0840 36.6960 ;
    END
  END u[68]
  PIN u[69]
    DIRECTION INPUT ;
    USE SIGNAL ;
    PORT
      LAYER M4 ;
        RECT 0.0000 37.1520 0.0840 37.1760 ;
    END
  END u[69]
  PIN u[6]
    DIRECTION INPUT ;
    USE SIGNAL ;
    PORT
      LAYER M4 ;
        RECT 0.0000 9.0240 0.0840 9.0480 ;
    END
  END u[6]
  PIN u[70]
    DIRECTION INPUT ;
    USE SIGNAL ;
    PORT
      LAYER M4 ;
        RECT 0.0000 37.5360 0.0840 37.5600 ;
    END
  END u[70]
  PIN u[71]
    DIRECTION INPUT ;
    USE SIGNAL ;
    PORT
      LAYER M4 ;
        RECT 0.0000 38.0160 0.0840 38.0400 ;
    END
  END u[71]
  PIN u[72]
    DIRECTION INPUT ;
    USE SIGNAL ;
    PORT
      LAYER M4 ;
        RECT 0.0000 38.4960 0.0840 38.5200 ;
    END
  END u[72]
  PIN u[73]
    DIRECTION INPUT ;
    USE SIGNAL ;
    PORT
      LAYER M4 ;
        RECT 0.0000 38.8800 0.0840 38.9040 ;
    END
  END u[73]
  PIN u[74]
    DIRECTION INPUT ;
    USE SIGNAL ;
    PORT
      LAYER M4 ;
        RECT 0.0000 39.3600 0.0840 39.3840 ;
    END
  END u[74]
  PIN u[75]
    DIRECTION INPUT ;
    USE SIGNAL ;
    PORT
      LAYER M4 ;
        RECT 0.0000 39.8400 0.0840 39.8640 ;
    END
  END u[75]
  PIN u[76]
    DIRECTION INPUT ;
    USE SIGNAL ;
    PORT
      LAYER M4 ;
        RECT 0.0000 40.2240 0.0840 40.2480 ;
    END
  END u[76]
  PIN u[77]
    DIRECTION INPUT ;
    USE SIGNAL ;
    PORT
      LAYER M4 ;
        RECT 0.0000 40.7040 0.0840 40.7280 ;
    END
  END u[77]
  PIN u[78]
    DIRECTION INPUT ;
    USE SIGNAL ;
    PORT
      LAYER M4 ;
        RECT 0.0000 41.0880 0.0840 41.1120 ;
    END
  END u[78]
  PIN u[79]
    DIRECTION INPUT ;
    USE SIGNAL ;
    PORT
      LAYER M4 ;
        RECT 0.0000 41.5680 0.0840 41.5920 ;
    END
  END u[79]
  PIN u[7]
    DIRECTION INPUT ;
    USE SIGNAL ;
    PORT
      LAYER M4 ;
        RECT 0.0000 9.4080 0.0840 9.4320 ;
    END
  END u[7]
  PIN u[80]
    DIRECTION INPUT ;
    USE SIGNAL ;
    PORT
      LAYER M4 ;
        RECT 0.0000 42.0480 0.0840 42.0720 ;
    END
  END u[80]
  PIN u[81]
    DIRECTION INPUT ;
    USE SIGNAL ;
    PORT
      LAYER M4 ;
        RECT 0.0000 42.4320 0.0840 42.4560 ;
    END
  END u[81]
  PIN u[82]
    DIRECTION INPUT ;
    USE SIGNAL ;
    PORT
      LAYER M4 ;
        RECT 0.0000 42.9120 0.0840 42.9360 ;
    END
  END u[82]
  PIN u[83]
    DIRECTION INPUT ;
    USE SIGNAL ;
    PORT
      LAYER M4 ;
        RECT 0.0000 43.3920 0.0840 43.4160 ;
    END
  END u[83]
  PIN u[84]
    DIRECTION INPUT ;
    USE SIGNAL ;
    PORT
      LAYER M4 ;
        RECT 0.0000 43.7760 0.0840 43.8000 ;
    END
  END u[84]
  PIN u[85]
    DIRECTION INPUT ;
    USE SIGNAL ;
    PORT
      LAYER M4 ;
        RECT 0.0000 44.2560 0.0840 44.2800 ;
    END
  END u[85]
  PIN u[86]
    DIRECTION INPUT ;
    USE SIGNAL ;
    PORT
      LAYER M4 ;
        RECT 0.0000 44.7360 0.0840 44.7600 ;
    END
  END u[86]
  PIN u[87]
    DIRECTION INPUT ;
    USE SIGNAL ;
    PORT
      LAYER M4 ;
        RECT 0.0000 45.1200 0.0840 45.1440 ;
    END
  END u[87]
  PIN u[88]
    DIRECTION INPUT ;
    USE SIGNAL ;
    PORT
      LAYER M4 ;
        RECT 0.0000 45.6000 0.0840 45.6240 ;
    END
  END u[88]
  PIN u[89]
    DIRECTION INPUT ;
    USE SIGNAL ;
    PORT
      LAYER M4 ;
        RECT 0.0000 46.0800 0.0840 46.1040 ;
    END
  END u[89]
  PIN u[8]
    DIRECTION INPUT ;
    USE SIGNAL ;
    PORT
      LAYER M4 ;
        RECT 0.0000 9.8880 0.0840 9.9120 ;
    END
  END u[8]
  PIN u[90]
    DIRECTION INPUT ;
    USE SIGNAL ;
    PORT
      LAYER M4 ;
        RECT 0.0000 46.4640 0.0840 46.4880 ;
    END
  END u[90]
  PIN u[91]
    DIRECTION INPUT ;
    USE SIGNAL ;
    PORT
      LAYER M4 ;
        RECT 0.0000 46.9440 0.0840 46.9680 ;
    END
  END u[91]
  PIN u[92]
    DIRECTION INPUT ;
    USE SIGNAL ;
    PORT
      LAYER M4 ;
        RECT 0.0000 47.4240 0.0840 47.4480 ;
    END
  END u[92]
  PIN u[93]
    DIRECTION INPUT ;
    USE SIGNAL ;
    PORT
      LAYER M4 ;
        RECT 0.0000 47.8080 0.0840 47.8320 ;
    END
  END u[93]
  PIN u[94]
    DIRECTION INPUT ;
    USE SIGNAL ;
    PORT
      LAYER M4 ;
        RECT 0.0000 48.2880 0.0840 48.3120 ;
    END
  END u[94]
  PIN u[95]
    DIRECTION INPUT ;
    USE SIGNAL ;
    PORT
      LAYER M4 ;
        RECT 0.0000 48.6720 0.0840 48.6960 ;
    END
  END u[95]
  PIN u[96]
    DIRECTION INPUT ;
    USE SIGNAL ;
    PORT
      LAYER M4 ;
        RECT 0.0000 49.1520 0.0840 49.1760 ;
    END
  END u[96]
  PIN u[97]
    DIRECTION INPUT ;
    USE SIGNAL ;
    PORT
      LAYER M4 ;
        RECT 0.0000 49.6320 0.0840 49.6560 ;
    END
  END u[97]
  PIN u[98]
    DIRECTION INPUT ;
    USE SIGNAL ;
    PORT
      LAYER M4 ;
        RECT 0.0000 50.0160 0.0840 50.0400 ;
    END
  END u[98]
  PIN u[99]
    DIRECTION INPUT ;
    USE SIGNAL ;
    PORT
      LAYER M4 ;
        RECT 0.0000 50.4960 0.0840 50.5200 ;
    END
  END u[99]
  PIN u[9]
    DIRECTION INPUT ;
    USE SIGNAL ;
    PORT
      LAYER M4 ;
        RECT 0.0000 10.3680 0.0840 10.3920 ;
    END
  END u[9]
  PIN u_i[0]
    DIRECTION INPUT ;
    USE SIGNAL ;
    PORT
      LAYER M4 ;
        RECT 0.0000 4.9920 0.0840 5.0160 ;
    END
  END u_i[0]
  PIN u_i[1]
    DIRECTION INPUT ;
    USE SIGNAL ;
    PORT
      LAYER M4 ;
        RECT 0.0000 5.3760 0.0840 5.4000 ;
    END
  END u_i[1]
  PIN u_i[2]
    DIRECTION INPUT ;
    USE SIGNAL ;
    PORT
      LAYER M4 ;
        RECT 0.0000 5.8560 0.0840 5.8800 ;
    END
  END u_i[2]
  PIN u_v
    DIRECTION INPUT ;
    USE SIGNAL ;
    PORT
      LAYER M4 ;
        RECT 0.0000 4.5120 0.0840 4.5360 ;
    END
  END u_v
  PIN um_b
    DIRECTION INPUT ;
    USE SIGNAL ;
    PORT
      LAYER M4 ;
        RECT 0.0000 121.4400 0.0840 121.4640 ;
    END
  END um_b
  PIN um_i[0]
    DIRECTION INPUT ;
    USE SIGNAL ;
    PORT
      LAYER M4 ;
        RECT 0.0000 121.9200 0.0840 121.9440 ;
    END
  END um_i[0]
  PIN um_i[1]
    DIRECTION INPUT ;
    USE SIGNAL ;
    PORT
      LAYER M4 ;
        RECT 0.0000 122.4000 0.0840 122.4240 ;
    END
  END um_i[1]
  PIN um_i[2]
    DIRECTION INPUT ;
    USE SIGNAL ;
    PORT
      LAYER M4 ;
        RECT 0.0000 122.7840 0.0840 122.8080 ;
    END
  END um_i[2]
  PIN um_i[3]
    DIRECTION INPUT ;
    USE SIGNAL ;
    PORT
      LAYER M4 ;
        RECT 0.0000 123.2640 0.0840 123.2880 ;
    END
  END um_i[3]
  PIN um_i[4]
    DIRECTION INPUT ;
    USE SIGNAL ;
    PORT
      LAYER M4 ;
        RECT 0.0000 123.7440 0.0840 123.7680 ;
    END
  END um_i[4]
  PIN um_i[5]
    DIRECTION INPUT ;
    USE SIGNAL ;
    PORT
      LAYER M4 ;
        RECT 0.0000 124.1280 0.0840 124.1520 ;
    END
  END um_i[5]
  PIN um_i[6]
    DIRECTION INPUT ;
    USE SIGNAL ;
    PORT
      LAYER M4 ;
        RECT 0.0000 124.6080 0.0840 124.6320 ;
    END
  END um_i[6]
  PIN um_i[7]
    DIRECTION INPUT ;
    USE SIGNAL ;
    PORT
      LAYER M4 ;
        RECT 0.0000 125.0880 0.0840 125.1120 ;
    END
  END um_i[7]
  PIN um_q
    DIRECTION INPUT ;
    USE SIGNAL ;
    PORT
      LAYER M4 ;
        RECT 0.0000 121.0560 0.0840 121.0800 ;
    END
  END um_q
  PIN um_v
    DIRECTION INPUT ;
    USE SIGNAL ;
    PORT
      LAYER M4 ;
        RECT 0.0000 120.5760 0.0840 120.6000 ;
    END
  END um_v
  PIN xf[0]
    DIRECTION OUTPUT ;
    USE SIGNAL ;
    PORT
      LAYER M5 ;
        RECT 156.6240 129.5160 156.6480 129.6000 ;
    END
  END xf[0]
  PIN xf[100]
    DIRECTION OUTPUT ;
    USE SIGNAL ;
    PORT
      LAYER M5 ;
        RECT 101.7120 129.5160 101.7360 129.6000 ;
    END
  END xf[100]
  PIN xf[101]
    DIRECTION OUTPUT ;
    USE SIGNAL ;
    PORT
      LAYER M3 ;
        RECT 101.1960 129.5620 101.2140 129.6000 ;
    END
  END xf[101]
  PIN xf[102]
    DIRECTION OUTPUT ;
    USE SIGNAL ;
    PORT
      LAYER M5 ;
        RECT 100.6560 129.5160 100.6800 129.6000 ;
    END
  END xf[102]
  PIN xf[103]
    DIRECTION OUTPUT ;
    USE SIGNAL ;
    PORT
      LAYER M3 ;
        RECT 100.1160 129.5620 100.1340 129.6000 ;
    END
  END xf[103]
  PIN xf[104]
    DIRECTION OUTPUT ;
    USE SIGNAL ;
    PORT
      LAYER M5 ;
        RECT 99.5040 129.5160 99.5280 129.6000 ;
    END
  END xf[104]
  PIN xf[105]
    DIRECTION OUTPUT ;
    USE SIGNAL ;
    PORT
      LAYER M3 ;
        RECT 99.0360 129.5620 99.0540 129.6000 ;
    END
  END xf[105]
  PIN xf[106]
    DIRECTION OUTPUT ;
    USE SIGNAL ;
    PORT
      LAYER M5 ;
        RECT 98.4480 129.5160 98.4720 129.6000 ;
    END
  END xf[106]
  PIN xf[107]
    DIRECTION OUTPUT ;
    USE SIGNAL ;
    PORT
      LAYER M3 ;
        RECT 97.8840 129.5620 97.9020 129.6000 ;
    END
  END xf[107]
  PIN xf[108]
    DIRECTION OUTPUT ;
    USE SIGNAL ;
    PORT
      LAYER M5 ;
        RECT 97.3920 129.5160 97.4160 129.6000 ;
    END
  END xf[108]
  PIN xf[109]
    DIRECTION OUTPUT ;
    USE SIGNAL ;
    PORT
      LAYER M3 ;
        RECT 96.8040 129.5620 96.8220 129.6000 ;
    END
  END xf[109]
  PIN xf[10]
    DIRECTION OUTPUT ;
    USE SIGNAL ;
    PORT
      LAYER M5 ;
        RECT 151.1520 129.5160 151.1760 129.6000 ;
    END
  END xf[10]
  PIN xf[110]
    DIRECTION OUTPUT ;
    USE SIGNAL ;
    PORT
      LAYER M5 ;
        RECT 96.2400 129.5160 96.2640 129.6000 ;
    END
  END xf[110]
  PIN xf[111]
    DIRECTION OUTPUT ;
    USE SIGNAL ;
    PORT
      LAYER M3 ;
        RECT 95.7240 129.5620 95.7420 129.6000 ;
    END
  END xf[111]
  PIN xf[112]
    DIRECTION OUTPUT ;
    USE SIGNAL ;
    PORT
      LAYER M5 ;
        RECT 95.1840 129.5160 95.2080 129.6000 ;
    END
  END xf[112]
  PIN xf[113]
    DIRECTION OUTPUT ;
    USE SIGNAL ;
    PORT
      LAYER M3 ;
        RECT 94.6440 129.5620 94.6620 129.6000 ;
    END
  END xf[113]
  PIN xf[114]
    DIRECTION OUTPUT ;
    USE SIGNAL ;
    PORT
      LAYER M5 ;
        RECT 94.0320 129.5160 94.0560 129.6000 ;
    END
  END xf[114]
  PIN xf[115]
    DIRECTION OUTPUT ;
    USE SIGNAL ;
    PORT
      LAYER M3 ;
        RECT 93.4920 129.5620 93.5100 129.6000 ;
    END
  END xf[115]
  PIN xf[116]
    DIRECTION OUTPUT ;
    USE SIGNAL ;
    PORT
      LAYER M5 ;
        RECT 92.9760 129.5160 93.0000 129.6000 ;
    END
  END xf[116]
  PIN xf[117]
    DIRECTION OUTPUT ;
    USE SIGNAL ;
    PORT
      LAYER M3 ;
        RECT 92.4120 129.5620 92.4300 129.6000 ;
    END
  END xf[117]
  PIN xf[118]
    DIRECTION OUTPUT ;
    USE SIGNAL ;
    PORT
      LAYER M5 ;
        RECT 91.8240 129.5160 91.8480 129.6000 ;
    END
  END xf[118]
  PIN xf[119]
    DIRECTION OUTPUT ;
    USE SIGNAL ;
    PORT
      LAYER M3 ;
        RECT 91.3320 129.5620 91.3500 129.6000 ;
    END
  END xf[119]
  PIN xf[11]
    DIRECTION OUTPUT ;
    USE SIGNAL ;
    PORT
      LAYER M3 ;
        RECT 150.5880 129.5620 150.6060 129.6000 ;
    END
  END xf[11]
  PIN xf[120]
    DIRECTION OUTPUT ;
    USE SIGNAL ;
    PORT
      LAYER M5 ;
        RECT 90.7680 129.5160 90.7920 129.6000 ;
    END
  END xf[120]
  PIN xf[121]
    DIRECTION OUTPUT ;
    USE SIGNAL ;
    PORT
      LAYER M3 ;
        RECT 90.2520 129.5620 90.2700 129.6000 ;
    END
  END xf[121]
  PIN xf[122]
    DIRECTION OUTPUT ;
    USE SIGNAL ;
    PORT
      LAYER M5 ;
        RECT 89.6160 129.5160 89.6400 129.6000 ;
    END
  END xf[122]
  PIN xf[123]
    DIRECTION OUTPUT ;
    USE SIGNAL ;
    PORT
      LAYER M3 ;
        RECT 89.1000 129.5620 89.1180 129.6000 ;
    END
  END xf[123]
  PIN xf[124]
    DIRECTION OUTPUT ;
    USE SIGNAL ;
    PORT
      LAYER M5 ;
        RECT 88.5600 129.5160 88.5840 129.6000 ;
    END
  END xf[124]
  PIN xf[125]
    DIRECTION OUTPUT ;
    USE SIGNAL ;
    PORT
      LAYER M3 ;
        RECT 88.0200 129.5620 88.0380 129.6000 ;
    END
  END xf[125]
  PIN xf[126]
    DIRECTION OUTPUT ;
    USE SIGNAL ;
    PORT
      LAYER M5 ;
        RECT 87.5040 129.5160 87.5280 129.6000 ;
    END
  END xf[126]
  PIN xf[127]
    DIRECTION OUTPUT ;
    USE SIGNAL ;
    PORT
      LAYER M3 ;
        RECT 85.7880 129.5620 85.8060 129.6000 ;
    END
  END xf[127]
  PIN xf[128]
    DIRECTION OUTPUT ;
    USE SIGNAL ;
    PORT
      LAYER M5 ;
        RECT 85.2960 129.5160 85.3200 129.6000 ;
    END
  END xf[128]
  PIN xf[129]
    DIRECTION OUTPUT ;
    USE SIGNAL ;
    PORT
      LAYER M3 ;
        RECT 84.7080 129.5620 84.7260 129.6000 ;
    END
  END xf[129]
  PIN xf[12]
    DIRECTION OUTPUT ;
    USE SIGNAL ;
    PORT
      LAYER M5 ;
        RECT 150.0960 129.5160 150.1200 129.6000 ;
    END
  END xf[12]
  PIN xf[130]
    DIRECTION OUTPUT ;
    USE SIGNAL ;
    PORT
      LAYER M5 ;
        RECT 84.1440 129.5160 84.1680 129.6000 ;
    END
  END xf[130]
  PIN xf[131]
    DIRECTION OUTPUT ;
    USE SIGNAL ;
    PORT
      LAYER M3 ;
        RECT 83.6280 129.5620 83.6460 129.6000 ;
    END
  END xf[131]
  PIN xf[132]
    DIRECTION OUTPUT ;
    USE SIGNAL ;
    PORT
      LAYER M5 ;
        RECT 83.0880 129.5160 83.1120 129.6000 ;
    END
  END xf[132]
  PIN xf[133]
    DIRECTION OUTPUT ;
    USE SIGNAL ;
    PORT
      LAYER M3 ;
        RECT 82.5480 129.5620 82.5660 129.6000 ;
    END
  END xf[133]
  PIN xf[134]
    DIRECTION OUTPUT ;
    USE SIGNAL ;
    PORT
      LAYER M5 ;
        RECT 81.9360 129.5160 81.9600 129.6000 ;
    END
  END xf[134]
  PIN xf[135]
    DIRECTION OUTPUT ;
    USE SIGNAL ;
    PORT
      LAYER M3 ;
        RECT 81.3960 129.5620 81.4140 129.6000 ;
    END
  END xf[135]
  PIN xf[136]
    DIRECTION OUTPUT ;
    USE SIGNAL ;
    PORT
      LAYER M5 ;
        RECT 80.8800 129.5160 80.9040 129.6000 ;
    END
  END xf[136]
  PIN xf[137]
    DIRECTION OUTPUT ;
    USE SIGNAL ;
    PORT
      LAYER M3 ;
        RECT 80.3160 129.5620 80.3340 129.6000 ;
    END
  END xf[137]
  PIN xf[138]
    DIRECTION OUTPUT ;
    USE SIGNAL ;
    PORT
      LAYER M5 ;
        RECT 79.7280 129.5160 79.7520 129.6000 ;
    END
  END xf[138]
  PIN xf[139]
    DIRECTION OUTPUT ;
    USE SIGNAL ;
    PORT
      LAYER M3 ;
        RECT 79.2360 129.5620 79.2540 129.6000 ;
    END
  END xf[139]
  PIN xf[13]
    DIRECTION OUTPUT ;
    USE SIGNAL ;
    PORT
      LAYER M3 ;
        RECT 149.5080 129.5620 149.5260 129.6000 ;
    END
  END xf[13]
  PIN xf[140]
    DIRECTION OUTPUT ;
    USE SIGNAL ;
    PORT
      LAYER M5 ;
        RECT 78.6720 129.5160 78.6960 129.6000 ;
    END
  END xf[140]
  PIN xf[141]
    DIRECTION OUTPUT ;
    USE SIGNAL ;
    PORT
      LAYER M3 ;
        RECT 78.1560 129.5620 78.1740 129.6000 ;
    END
  END xf[141]
  PIN xf[142]
    DIRECTION OUTPUT ;
    USE SIGNAL ;
    PORT
      LAYER M5 ;
        RECT 77.6160 129.5160 77.6400 129.6000 ;
    END
  END xf[142]
  PIN xf[143]
    DIRECTION OUTPUT ;
    USE SIGNAL ;
    PORT
      LAYER M3 ;
        RECT 77.0040 129.5620 77.0220 129.6000 ;
    END
  END xf[143]
  PIN xf[144]
    DIRECTION OUTPUT ;
    USE SIGNAL ;
    PORT
      LAYER M5 ;
        RECT 76.4640 129.5160 76.4880 129.6000 ;
    END
  END xf[144]
  PIN xf[145]
    DIRECTION OUTPUT ;
    USE SIGNAL ;
    PORT
      LAYER M3 ;
        RECT 75.9240 129.5620 75.9420 129.6000 ;
    END
  END xf[145]
  PIN xf[146]
    DIRECTION OUTPUT ;
    USE SIGNAL ;
    PORT
      LAYER M5 ;
        RECT 75.4080 129.5160 75.4320 129.6000 ;
    END
  END xf[146]
  PIN xf[147]
    DIRECTION OUTPUT ;
    USE SIGNAL ;
    PORT
      LAYER M3 ;
        RECT 74.8440 129.5620 74.8620 129.6000 ;
    END
  END xf[147]
  PIN xf[148]
    DIRECTION OUTPUT ;
    USE SIGNAL ;
    PORT
      LAYER M5 ;
        RECT 74.2560 129.5160 74.2800 129.6000 ;
    END
  END xf[148]
  PIN xf[149]
    DIRECTION OUTPUT ;
    USE SIGNAL ;
    PORT
      LAYER M3 ;
        RECT 73.7640 129.5620 73.7820 129.6000 ;
    END
  END xf[149]
  PIN xf[14]
    DIRECTION OUTPUT ;
    USE SIGNAL ;
    PORT
      LAYER M5 ;
        RECT 148.9440 129.5160 148.9680 129.6000 ;
    END
  END xf[14]
  PIN xf[150]
    DIRECTION OUTPUT ;
    USE SIGNAL ;
    PORT
      LAYER M5 ;
        RECT 73.2000 129.5160 73.2240 129.6000 ;
    END
  END xf[150]
  PIN xf[151]
    DIRECTION OUTPUT ;
    USE SIGNAL ;
    PORT
      LAYER M3 ;
        RECT 72.6120 129.5620 72.6300 129.6000 ;
    END
  END xf[151]
  PIN xf[152]
    DIRECTION OUTPUT ;
    USE SIGNAL ;
    PORT
      LAYER M5 ;
        RECT 72.0480 129.5160 72.0720 129.6000 ;
    END
  END xf[152]
  PIN xf[153]
    DIRECTION OUTPUT ;
    USE SIGNAL ;
    PORT
      LAYER M3 ;
        RECT 71.5320 129.5620 71.5500 129.6000 ;
    END
  END xf[153]
  PIN xf[154]
    DIRECTION OUTPUT ;
    USE SIGNAL ;
    PORT
      LAYER M5 ;
        RECT 70.9920 129.5160 71.0160 129.6000 ;
    END
  END xf[154]
  PIN xf[155]
    DIRECTION OUTPUT ;
    USE SIGNAL ;
    PORT
      LAYER M3 ;
        RECT 70.4520 129.5620 70.4700 129.6000 ;
    END
  END xf[155]
  PIN xf[156]
    DIRECTION OUTPUT ;
    USE SIGNAL ;
    PORT
      LAYER M5 ;
        RECT 69.9360 129.5160 69.9600 129.6000 ;
    END
  END xf[156]
  PIN xf[157]
    DIRECTION OUTPUT ;
    USE SIGNAL ;
    PORT
      LAYER M3 ;
        RECT 69.3720 129.5620 69.3900 129.6000 ;
    END
  END xf[157]
  PIN xf[158]
    DIRECTION OUTPUT ;
    USE SIGNAL ;
    PORT
      LAYER M5 ;
        RECT 68.7840 129.5160 68.8080 129.6000 ;
    END
  END xf[158]
  PIN xf[159]
    DIRECTION OUTPUT ;
    USE SIGNAL ;
    PORT
      LAYER M3 ;
        RECT 68.2200 129.5620 68.2380 129.6000 ;
    END
  END xf[159]
  PIN xf[15]
    DIRECTION OUTPUT ;
    USE SIGNAL ;
    PORT
      LAYER M3 ;
        RECT 148.4280 129.5620 148.4460 129.6000 ;
    END
  END xf[15]
  PIN xf[160]
    DIRECTION OUTPUT ;
    USE SIGNAL ;
    PORT
      LAYER M5 ;
        RECT 67.7280 129.5160 67.7520 129.6000 ;
    END
  END xf[160]
  PIN xf[161]
    DIRECTION OUTPUT ;
    USE SIGNAL ;
    PORT
      LAYER M3 ;
        RECT 67.1400 129.5620 67.1580 129.6000 ;
    END
  END xf[161]
  PIN xf[162]
    DIRECTION OUTPUT ;
    USE SIGNAL ;
    PORT
      LAYER M5 ;
        RECT 66.5760 129.5160 66.6000 129.6000 ;
    END
  END xf[162]
  PIN xf[163]
    DIRECTION OUTPUT ;
    USE SIGNAL ;
    PORT
      LAYER M3 ;
        RECT 66.0600 129.5620 66.0780 129.6000 ;
    END
  END xf[163]
  PIN xf[164]
    DIRECTION OUTPUT ;
    USE SIGNAL ;
    PORT
      LAYER M5 ;
        RECT 65.5200 129.5160 65.5440 129.6000 ;
    END
  END xf[164]
  PIN xf[165]
    DIRECTION OUTPUT ;
    USE SIGNAL ;
    PORT
      LAYER M3 ;
        RECT 64.9800 129.5620 64.9980 129.6000 ;
    END
  END xf[165]
  PIN xf[166]
    DIRECTION OUTPUT ;
    USE SIGNAL ;
    PORT
      LAYER M5 ;
        RECT 64.3680 129.5160 64.3920 129.6000 ;
    END
  END xf[166]
  PIN xf[167]
    DIRECTION OUTPUT ;
    USE SIGNAL ;
    PORT
      LAYER M3 ;
        RECT 63.8280 129.5620 63.8460 129.6000 ;
    END
  END xf[167]
  PIN xf[168]
    DIRECTION OUTPUT ;
    USE SIGNAL ;
    PORT
      LAYER M5 ;
        RECT 63.3120 129.5160 63.3360 129.6000 ;
    END
  END xf[168]
  PIN xf[169]
    DIRECTION OUTPUT ;
    USE SIGNAL ;
    PORT
      LAYER M3 ;
        RECT 62.7480 129.5620 62.7660 129.6000 ;
    END
  END xf[169]
  PIN xf[16]
    DIRECTION OUTPUT ;
    USE SIGNAL ;
    PORT
      LAYER M5 ;
        RECT 147.8880 129.5160 147.9120 129.6000 ;
    END
  END xf[16]
  PIN xf[170]
    DIRECTION OUTPUT ;
    USE SIGNAL ;
    PORT
      LAYER M5 ;
        RECT 62.1600 129.5160 62.1840 129.6000 ;
    END
  END xf[170]
  PIN xf[171]
    DIRECTION OUTPUT ;
    USE SIGNAL ;
    PORT
      LAYER M3 ;
        RECT 61.6680 129.5620 61.6860 129.6000 ;
    END
  END xf[171]
  PIN xf[172]
    DIRECTION OUTPUT ;
    USE SIGNAL ;
    PORT
      LAYER M5 ;
        RECT 61.1040 129.5160 61.1280 129.6000 ;
    END
  END xf[172]
  PIN xf[173]
    DIRECTION OUTPUT ;
    USE SIGNAL ;
    PORT
      LAYER M3 ;
        RECT 60.5880 129.5620 60.6060 129.6000 ;
    END
  END xf[173]
  PIN xf[174]
    DIRECTION OUTPUT ;
    USE SIGNAL ;
    PORT
      LAYER M5 ;
        RECT 60.0480 129.5160 60.0720 129.6000 ;
    END
  END xf[174]
  PIN xf[175]
    DIRECTION OUTPUT ;
    USE SIGNAL ;
    PORT
      LAYER M3 ;
        RECT 59.4360 129.5620 59.4540 129.6000 ;
    END
  END xf[175]
  PIN xf[176]
    DIRECTION OUTPUT ;
    USE SIGNAL ;
    PORT
      LAYER M5 ;
        RECT 58.8960 129.5160 58.9200 129.6000 ;
    END
  END xf[176]
  PIN xf[177]
    DIRECTION OUTPUT ;
    USE SIGNAL ;
    PORT
      LAYER M3 ;
        RECT 58.3560 129.5620 58.3740 129.6000 ;
    END
  END xf[177]
  PIN xf[178]
    DIRECTION OUTPUT ;
    USE SIGNAL ;
    PORT
      LAYER M5 ;
        RECT 57.8400 129.5160 57.8640 129.6000 ;
    END
  END xf[178]
  PIN xf[179]
    DIRECTION OUTPUT ;
    USE SIGNAL ;
    PORT
      LAYER M3 ;
        RECT 57.2760 129.5620 57.2940 129.6000 ;
    END
  END xf[179]
  PIN xf[17]
    DIRECTION OUTPUT ;
    USE SIGNAL ;
    PORT
      LAYER M3 ;
        RECT 147.3480 129.5620 147.3660 129.6000 ;
    END
  END xf[17]
  PIN xf[180]
    DIRECTION OUTPUT ;
    USE SIGNAL ;
    PORT
      LAYER M5 ;
        RECT 56.6880 129.5160 56.7120 129.6000 ;
    END
  END xf[180]
  PIN xf[181]
    DIRECTION OUTPUT ;
    USE SIGNAL ;
    PORT
      LAYER M3 ;
        RECT 56.1960 129.5620 56.2140 129.6000 ;
    END
  END xf[181]
  PIN xf[182]
    DIRECTION OUTPUT ;
    USE SIGNAL ;
    PORT
      LAYER M5 ;
        RECT 55.6320 129.5160 55.6560 129.6000 ;
    END
  END xf[182]
  PIN xf[183]
    DIRECTION OUTPUT ;
    USE SIGNAL ;
    PORT
      LAYER M3 ;
        RECT 55.0440 129.5620 55.0620 129.6000 ;
    END
  END xf[183]
  PIN xf[184]
    DIRECTION OUTPUT ;
    USE SIGNAL ;
    PORT
      LAYER M5 ;
        RECT 54.4800 129.5160 54.5040 129.6000 ;
    END
  END xf[184]
  PIN xf[185]
    DIRECTION OUTPUT ;
    USE SIGNAL ;
    PORT
      LAYER M3 ;
        RECT 53.9640 129.5620 53.9820 129.6000 ;
    END
  END xf[185]
  PIN xf[186]
    DIRECTION OUTPUT ;
    USE SIGNAL ;
    PORT
      LAYER M5 ;
        RECT 53.4240 129.5160 53.4480 129.6000 ;
    END
  END xf[186]
  PIN xf[187]
    DIRECTION OUTPUT ;
    USE SIGNAL ;
    PORT
      LAYER M3 ;
        RECT 52.8840 129.5620 52.9020 129.6000 ;
    END
  END xf[187]
  PIN xf[188]
    DIRECTION OUTPUT ;
    USE SIGNAL ;
    PORT
      LAYER M5 ;
        RECT 52.3680 129.5160 52.3920 129.6000 ;
    END
  END xf[188]
  PIN xf[189]
    DIRECTION OUTPUT ;
    USE SIGNAL ;
    PORT
      LAYER M3 ;
        RECT 51.8040 129.5620 51.8220 129.6000 ;
    END
  END xf[189]
  PIN xf[18]
    DIRECTION OUTPUT ;
    USE SIGNAL ;
    PORT
      LAYER M5 ;
        RECT 146.7360 129.5160 146.7600 129.6000 ;
    END
  END xf[18]
  PIN xf[190]
    DIRECTION OUTPUT ;
    USE SIGNAL ;
    PORT
      LAYER M5 ;
        RECT 51.2160 129.5160 51.2400 129.6000 ;
    END
  END xf[190]
  PIN xf[191]
    DIRECTION OUTPUT ;
    USE SIGNAL ;
    PORT
      LAYER M3 ;
        RECT 50.6520 129.5620 50.6700 129.6000 ;
    END
  END xf[191]
  PIN xf[192]
    DIRECTION OUTPUT ;
    USE SIGNAL ;
    PORT
      LAYER M5 ;
        RECT 50.1600 129.5160 50.1840 129.6000 ;
    END
  END xf[192]
  PIN xf[193]
    DIRECTION OUTPUT ;
    USE SIGNAL ;
    PORT
      LAYER M3 ;
        RECT 49.5720 129.5620 49.5900 129.6000 ;
    END
  END xf[193]
  PIN xf[194]
    DIRECTION OUTPUT ;
    USE SIGNAL ;
    PORT
      LAYER M5 ;
        RECT 49.0080 129.5160 49.0320 129.6000 ;
    END
  END xf[194]
  PIN xf[195]
    DIRECTION OUTPUT ;
    USE SIGNAL ;
    PORT
      LAYER M3 ;
        RECT 48.4920 129.5620 48.5100 129.6000 ;
    END
  END xf[195]
  PIN xf[196]
    DIRECTION OUTPUT ;
    USE SIGNAL ;
    PORT
      LAYER M5 ;
        RECT 47.9520 129.5160 47.9760 129.6000 ;
    END
  END xf[196]
  PIN xf[197]
    DIRECTION OUTPUT ;
    USE SIGNAL ;
    PORT
      LAYER M3 ;
        RECT 47.4120 129.5620 47.4300 129.6000 ;
    END
  END xf[197]
  PIN xf[198]
    DIRECTION OUTPUT ;
    USE SIGNAL ;
    PORT
      LAYER M5 ;
        RECT 46.8000 129.5160 46.8240 129.6000 ;
    END
  END xf[198]
  PIN xf[199]
    DIRECTION OUTPUT ;
    USE SIGNAL ;
    PORT
      LAYER M3 ;
        RECT 46.2600 129.5620 46.2780 129.6000 ;
    END
  END xf[199]
  PIN xf[19]
    DIRECTION OUTPUT ;
    USE SIGNAL ;
    PORT
      LAYER M3 ;
        RECT 146.1960 129.5620 146.2140 129.6000 ;
    END
  END xf[19]
  PIN xf[1]
    DIRECTION OUTPUT ;
    USE SIGNAL ;
    PORT
      LAYER M3 ;
        RECT 156.1320 129.5620 156.1500 129.6000 ;
    END
  END xf[1]
  PIN xf[200]
    DIRECTION OUTPUT ;
    USE SIGNAL ;
    PORT
      LAYER M5 ;
        RECT 45.7440 129.5160 45.7680 129.6000 ;
    END
  END xf[200]
  PIN xf[201]
    DIRECTION OUTPUT ;
    USE SIGNAL ;
    PORT
      LAYER M3 ;
        RECT 45.1800 129.5620 45.1980 129.6000 ;
    END
  END xf[201]
  PIN xf[202]
    DIRECTION OUTPUT ;
    USE SIGNAL ;
    PORT
      LAYER M5 ;
        RECT 44.5920 129.5160 44.6160 129.6000 ;
    END
  END xf[202]
  PIN xf[203]
    DIRECTION OUTPUT ;
    USE SIGNAL ;
    PORT
      LAYER M3 ;
        RECT 44.1000 129.5620 44.1180 129.6000 ;
    END
  END xf[203]
  PIN xf[204]
    DIRECTION OUTPUT ;
    USE SIGNAL ;
    PORT
      LAYER M5 ;
        RECT 43.5360 129.5160 43.5600 129.6000 ;
    END
  END xf[204]
  PIN xf[205]
    DIRECTION OUTPUT ;
    USE SIGNAL ;
    PORT
      LAYER M3 ;
        RECT 43.0200 129.5620 43.0380 129.6000 ;
    END
  END xf[205]
  PIN xf[206]
    DIRECTION OUTPUT ;
    USE SIGNAL ;
    PORT
      LAYER M5 ;
        RECT 42.4800 129.5160 42.5040 129.6000 ;
    END
  END xf[206]
  PIN xf[207]
    DIRECTION OUTPUT ;
    USE SIGNAL ;
    PORT
      LAYER M3 ;
        RECT 41.8680 129.5620 41.8860 129.6000 ;
    END
  END xf[207]
  PIN xf[208]
    DIRECTION OUTPUT ;
    USE SIGNAL ;
    PORT
      LAYER M5 ;
        RECT 41.3280 129.5160 41.3520 129.6000 ;
    END
  END xf[208]
  PIN xf[209]
    DIRECTION OUTPUT ;
    USE SIGNAL ;
    PORT
      LAYER M3 ;
        RECT 40.7880 129.5620 40.8060 129.6000 ;
    END
  END xf[209]
  PIN xf[20]
    DIRECTION OUTPUT ;
    USE SIGNAL ;
    PORT
      LAYER M5 ;
        RECT 145.6800 129.5160 145.7040 129.6000 ;
    END
  END xf[20]
  PIN xf[210]
    DIRECTION OUTPUT ;
    USE SIGNAL ;
    PORT
      LAYER M5 ;
        RECT 40.2720 129.5160 40.2960 129.6000 ;
    END
  END xf[210]
  PIN xf[211]
    DIRECTION OUTPUT ;
    USE SIGNAL ;
    PORT
      LAYER M3 ;
        RECT 39.7080 129.5620 39.7260 129.6000 ;
    END
  END xf[211]
  PIN xf[212]
    DIRECTION OUTPUT ;
    USE SIGNAL ;
    PORT
      LAYER M5 ;
        RECT 39.1200 129.5160 39.1440 129.6000 ;
    END
  END xf[212]
  PIN xf[213]
    DIRECTION OUTPUT ;
    USE SIGNAL ;
    PORT
      LAYER M3 ;
        RECT 38.6280 129.5620 38.6460 129.6000 ;
    END
  END xf[213]
  PIN xf[214]
    DIRECTION OUTPUT ;
    USE SIGNAL ;
    PORT
      LAYER M5 ;
        RECT 38.0640 129.5160 38.0880 129.6000 ;
    END
  END xf[214]
  PIN xf[215]
    DIRECTION OUTPUT ;
    USE SIGNAL ;
    PORT
      LAYER M3 ;
        RECT 37.4760 129.5620 37.4940 129.6000 ;
    END
  END xf[215]
  PIN xf[216]
    DIRECTION OUTPUT ;
    USE SIGNAL ;
    PORT
      LAYER M5 ;
        RECT 36.9120 129.5160 36.9360 129.6000 ;
    END
  END xf[216]
  PIN xf[217]
    DIRECTION OUTPUT ;
    USE SIGNAL ;
    PORT
      LAYER M3 ;
        RECT 36.3960 129.5620 36.4140 129.6000 ;
    END
  END xf[217]
  PIN xf[218]
    DIRECTION OUTPUT ;
    USE SIGNAL ;
    PORT
      LAYER M5 ;
        RECT 35.8560 129.5160 35.8800 129.6000 ;
    END
  END xf[218]
  PIN xf[219]
    DIRECTION OUTPUT ;
    USE SIGNAL ;
    PORT
      LAYER M3 ;
        RECT 35.3160 129.5620 35.3340 129.6000 ;
    END
  END xf[219]
  PIN xf[21]
    DIRECTION OUTPUT ;
    USE SIGNAL ;
    PORT
      LAYER M3 ;
        RECT 145.1160 129.5620 145.1340 129.6000 ;
    END
  END xf[21]
  PIN xf[220]
    DIRECTION OUTPUT ;
    USE SIGNAL ;
    PORT
      LAYER M5 ;
        RECT 34.8000 129.5160 34.8240 129.6000 ;
    END
  END xf[220]
  PIN xf[221]
    DIRECTION OUTPUT ;
    USE SIGNAL ;
    PORT
      LAYER M3 ;
        RECT 34.2360 129.5620 34.2540 129.6000 ;
    END
  END xf[221]
  PIN xf[222]
    DIRECTION OUTPUT ;
    USE SIGNAL ;
    PORT
      LAYER M5 ;
        RECT 33.6480 129.5160 33.6720 129.6000 ;
    END
  END xf[222]
  PIN xf[223]
    DIRECTION OUTPUT ;
    USE SIGNAL ;
    PORT
      LAYER M3 ;
        RECT 33.0840 129.5620 33.1020 129.6000 ;
    END
  END xf[223]
  PIN xf[224]
    DIRECTION OUTPUT ;
    USE SIGNAL ;
    PORT
      LAYER M5 ;
        RECT 32.5920 129.5160 32.6160 129.6000 ;
    END
  END xf[224]
  PIN xf[225]
    DIRECTION OUTPUT ;
    USE SIGNAL ;
    PORT
      LAYER M3 ;
        RECT 32.0040 129.5620 32.0220 129.6000 ;
    END
  END xf[225]
  PIN xf[226]
    DIRECTION OUTPUT ;
    USE SIGNAL ;
    PORT
      LAYER M5 ;
        RECT 31.4400 129.5160 31.4640 129.6000 ;
    END
  END xf[226]
  PIN xf[227]
    DIRECTION OUTPUT ;
    USE SIGNAL ;
    PORT
      LAYER M3 ;
        RECT 30.9240 129.5620 30.9420 129.6000 ;
    END
  END xf[227]
  PIN xf[228]
    DIRECTION OUTPUT ;
    USE SIGNAL ;
    PORT
      LAYER M5 ;
        RECT 30.3840 129.5160 30.4080 129.6000 ;
    END
  END xf[228]
  PIN xf[229]
    DIRECTION OUTPUT ;
    USE SIGNAL ;
    PORT
      LAYER M3 ;
        RECT 29.8440 129.5620 29.8620 129.6000 ;
    END
  END xf[229]
  PIN xf[22]
    DIRECTION OUTPUT ;
    USE SIGNAL ;
    PORT
      LAYER M5 ;
        RECT 144.5280 129.5160 144.5520 129.6000 ;
    END
  END xf[22]
  PIN xf[230]
    DIRECTION OUTPUT ;
    USE SIGNAL ;
    PORT
      LAYER M5 ;
        RECT 29.2320 129.5160 29.2560 129.6000 ;
    END
  END xf[230]
  PIN xf[231]
    DIRECTION OUTPUT ;
    USE SIGNAL ;
    PORT
      LAYER M3 ;
        RECT 28.6920 129.5620 28.7100 129.6000 ;
    END
  END xf[231]
  PIN xf[232]
    DIRECTION OUTPUT ;
    USE SIGNAL ;
    PORT
      LAYER M5 ;
        RECT 28.1760 129.5160 28.2000 129.6000 ;
    END
  END xf[232]
  PIN xf[233]
    DIRECTION OUTPUT ;
    USE SIGNAL ;
    PORT
      LAYER M3 ;
        RECT 27.6120 129.5620 27.6300 129.6000 ;
    END
  END xf[233]
  PIN xf[234]
    DIRECTION OUTPUT ;
    USE SIGNAL ;
    PORT
      LAYER M5 ;
        RECT 27.0240 129.5160 27.0480 129.6000 ;
    END
  END xf[234]
  PIN xf[235]
    DIRECTION OUTPUT ;
    USE SIGNAL ;
    PORT
      LAYER M3 ;
        RECT 26.5320 129.5620 26.5500 129.6000 ;
    END
  END xf[235]
  PIN xf[236]
    DIRECTION OUTPUT ;
    USE SIGNAL ;
    PORT
      LAYER M5 ;
        RECT 25.9680 129.5160 25.9920 129.6000 ;
    END
  END xf[236]
  PIN xf[237]
    DIRECTION OUTPUT ;
    USE SIGNAL ;
    PORT
      LAYER M3 ;
        RECT 25.4520 129.5620 25.4700 129.6000 ;
    END
  END xf[237]
  PIN xf[238]
    DIRECTION OUTPUT ;
    USE SIGNAL ;
    PORT
      LAYER M5 ;
        RECT 24.9120 129.5160 24.9360 129.6000 ;
    END
  END xf[238]
  PIN xf[239]
    DIRECTION OUTPUT ;
    USE SIGNAL ;
    PORT
      LAYER M3 ;
        RECT 24.3000 129.5620 24.3180 129.6000 ;
    END
  END xf[239]
  PIN xf[23]
    DIRECTION OUTPUT ;
    USE SIGNAL ;
    PORT
      LAYER M3 ;
        RECT 144.0360 129.5620 144.0540 129.6000 ;
    END
  END xf[23]
  PIN xf[240]
    DIRECTION OUTPUT ;
    USE SIGNAL ;
    PORT
      LAYER M5 ;
        RECT 23.7600 129.5160 23.7840 129.6000 ;
    END
  END xf[240]
  PIN xf[241]
    DIRECTION OUTPUT ;
    USE SIGNAL ;
    PORT
      LAYER M3 ;
        RECT 23.2200 129.5620 23.2380 129.6000 ;
    END
  END xf[241]
  PIN xf[242]
    DIRECTION OUTPUT ;
    USE SIGNAL ;
    PORT
      LAYER M5 ;
        RECT 22.7040 129.5160 22.7280 129.6000 ;
    END
  END xf[242]
  PIN xf[243]
    DIRECTION OUTPUT ;
    USE SIGNAL ;
    PORT
      LAYER M3 ;
        RECT 22.1400 129.5620 22.1580 129.6000 ;
    END
  END xf[243]
  PIN xf[244]
    DIRECTION OUTPUT ;
    USE SIGNAL ;
    PORT
      LAYER M5 ;
        RECT 21.5520 129.5160 21.5760 129.6000 ;
    END
  END xf[244]
  PIN xf[245]
    DIRECTION OUTPUT ;
    USE SIGNAL ;
    PORT
      LAYER M3 ;
        RECT 21.0600 129.5620 21.0780 129.6000 ;
    END
  END xf[245]
  PIN xf[246]
    DIRECTION OUTPUT ;
    USE SIGNAL ;
    PORT
      LAYER M5 ;
        RECT 20.4960 129.5160 20.5200 129.6000 ;
    END
  END xf[246]
  PIN xf[247]
    DIRECTION OUTPUT ;
    USE SIGNAL ;
    PORT
      LAYER M3 ;
        RECT 19.9080 129.5620 19.9260 129.6000 ;
    END
  END xf[247]
  PIN xf[248]
    DIRECTION OUTPUT ;
    USE SIGNAL ;
    PORT
      LAYER M5 ;
        RECT 19.3440 129.5160 19.3680 129.6000 ;
    END
  END xf[248]
  PIN xf[249]
    DIRECTION OUTPUT ;
    USE SIGNAL ;
    PORT
      LAYER M3 ;
        RECT 18.8280 129.5620 18.8460 129.6000 ;
    END
  END xf[249]
  PIN xf[24]
    DIRECTION OUTPUT ;
    USE SIGNAL ;
    PORT
      LAYER M5 ;
        RECT 143.4720 129.5160 143.4960 129.6000 ;
    END
  END xf[24]
  PIN xf[250]
    DIRECTION OUTPUT ;
    USE SIGNAL ;
    PORT
      LAYER M5 ;
        RECT 18.2880 129.5160 18.3120 129.6000 ;
    END
  END xf[250]
  PIN xf[251]
    DIRECTION OUTPUT ;
    USE SIGNAL ;
    PORT
      LAYER M3 ;
        RECT 17.7480 129.5620 17.7660 129.6000 ;
    END
  END xf[251]
  PIN xf[252]
    DIRECTION OUTPUT ;
    USE SIGNAL ;
    PORT
      LAYER M5 ;
        RECT 17.2320 129.5160 17.2560 129.6000 ;
    END
  END xf[252]
  PIN xf[253]
    DIRECTION OUTPUT ;
    USE SIGNAL ;
    PORT
      LAYER M3 ;
        RECT 16.6680 129.5620 16.6860 129.6000 ;
    END
  END xf[253]
  PIN xf[254]
    DIRECTION OUTPUT ;
    USE SIGNAL ;
    PORT
      LAYER M5 ;
        RECT 16.0800 129.5160 16.1040 129.6000 ;
    END
  END xf[254]
  PIN xf[255]
    DIRECTION OUTPUT ;
    USE SIGNAL ;
    PORT
      LAYER M3 ;
        RECT 15.5160 129.5620 15.5340 129.6000 ;
    END
  END xf[255]
  PIN xf[256]
    DIRECTION OUTPUT ;
    USE SIGNAL ;
    PORT
      LAYER M5 ;
        RECT 15.0240 129.5160 15.0480 129.6000 ;
    END
  END xf[256]
  PIN xf[257]
    DIRECTION OUTPUT ;
    USE SIGNAL ;
    PORT
      LAYER M3 ;
        RECT 14.4360 129.5620 14.4540 129.6000 ;
    END
  END xf[257]
  PIN xf[258]
    DIRECTION OUTPUT ;
    USE SIGNAL ;
    PORT
      LAYER M5 ;
        RECT 13.8720 129.5160 13.8960 129.6000 ;
    END
  END xf[258]
  PIN xf[259]
    DIRECTION OUTPUT ;
    USE SIGNAL ;
    PORT
      LAYER M3 ;
        RECT 13.3560 129.5620 13.3740 129.6000 ;
    END
  END xf[259]
  PIN xf[25]
    DIRECTION OUTPUT ;
    USE SIGNAL ;
    PORT
      LAYER M3 ;
        RECT 142.9560 129.5620 142.9740 129.6000 ;
    END
  END xf[25]
  PIN xf[260]
    DIRECTION OUTPUT ;
    USE SIGNAL ;
    PORT
      LAYER M5 ;
        RECT 12.8160 129.5160 12.8400 129.6000 ;
    END
  END xf[260]
  PIN xf[261]
    DIRECTION OUTPUT ;
    USE SIGNAL ;
    PORT
      LAYER M3 ;
        RECT 12.2760 129.5620 12.2940 129.6000 ;
    END
  END xf[261]
  PIN xf[262]
    DIRECTION OUTPUT ;
    USE SIGNAL ;
    PORT
      LAYER M5 ;
        RECT 11.6640 129.5160 11.6880 129.6000 ;
    END
  END xf[262]
  PIN xf[263]
    DIRECTION OUTPUT ;
    USE SIGNAL ;
    PORT
      LAYER M3 ;
        RECT 11.1240 129.5620 11.1420 129.6000 ;
    END
  END xf[263]
  PIN xf[264]
    DIRECTION OUTPUT ;
    USE SIGNAL ;
    PORT
      LAYER M5 ;
        RECT 10.6080 129.5160 10.6320 129.6000 ;
    END
  END xf[264]
  PIN xf[265]
    DIRECTION OUTPUT ;
    USE SIGNAL ;
    PORT
      LAYER M3 ;
        RECT 10.0440 129.5620 10.0620 129.6000 ;
    END
  END xf[265]
  PIN xf[266]
    DIRECTION OUTPUT ;
    USE SIGNAL ;
    PORT
      LAYER M5 ;
        RECT 9.4560 129.5160 9.4800 129.6000 ;
    END
  END xf[266]
  PIN xf[267]
    DIRECTION OUTPUT ;
    USE SIGNAL ;
    PORT
      LAYER M3 ;
        RECT 8.9640 129.5620 8.9820 129.6000 ;
    END
  END xf[267]
  PIN xf[268]
    DIRECTION OUTPUT ;
    USE SIGNAL ;
    PORT
      LAYER M5 ;
        RECT 8.4000 129.5160 8.4240 129.6000 ;
    END
  END xf[268]
  PIN xf[269]
    DIRECTION OUTPUT ;
    USE SIGNAL ;
    PORT
      LAYER M3 ;
        RECT 7.8840 129.5620 7.9020 129.6000 ;
    END
  END xf[269]
  PIN xf[26]
    DIRECTION OUTPUT ;
    USE SIGNAL ;
    PORT
      LAYER M5 ;
        RECT 142.3200 129.5160 142.3440 129.6000 ;
    END
  END xf[26]
  PIN xf[270]
    DIRECTION OUTPUT ;
    USE SIGNAL ;
    PORT
      LAYER M5 ;
        RECT 7.3440 129.5160 7.3680 129.6000 ;
    END
  END xf[270]
  PIN xf[271]
    DIRECTION OUTPUT ;
    USE SIGNAL ;
    PORT
      LAYER M3 ;
        RECT 6.7320 129.5620 6.7500 129.6000 ;
    END
  END xf[271]
  PIN xf[272]
    DIRECTION OUTPUT ;
    USE SIGNAL ;
    PORT
      LAYER M5 ;
        RECT 6.1920 129.5160 6.2160 129.6000 ;
    END
  END xf[272]
  PIN xf[273]
    DIRECTION OUTPUT ;
    USE SIGNAL ;
    PORT
      LAYER M3 ;
        RECT 5.6520 129.5620 5.6700 129.6000 ;
    END
  END xf[273]
  PIN xf[274]
    DIRECTION OUTPUT ;
    USE SIGNAL ;
    PORT
      LAYER M5 ;
        RECT 5.1360 129.5160 5.1600 129.6000 ;
    END
  END xf[274]
  PIN xf[275]
    DIRECTION OUTPUT ;
    USE SIGNAL ;
    PORT
      LAYER M3 ;
        RECT 4.5720 129.5620 4.5900 129.6000 ;
    END
  END xf[275]
  PIN xf[27]
    DIRECTION OUTPUT ;
    USE SIGNAL ;
    PORT
      LAYER M3 ;
        RECT 141.8040 129.5620 141.8220 129.6000 ;
    END
  END xf[27]
  PIN xf[28]
    DIRECTION OUTPUT ;
    USE SIGNAL ;
    PORT
      LAYER M5 ;
        RECT 141.2640 129.5160 141.2880 129.6000 ;
    END
  END xf[28]
  PIN xf[29]
    DIRECTION OUTPUT ;
    USE SIGNAL ;
    PORT
      LAYER M3 ;
        RECT 140.7240 129.5620 140.7420 129.6000 ;
    END
  END xf[29]
  PIN xf[2]
    DIRECTION OUTPUT ;
    USE SIGNAL ;
    PORT
      LAYER M5 ;
        RECT 155.5680 129.5160 155.5920 129.6000 ;
    END
  END xf[2]
  PIN xf[30]
    DIRECTION OUTPUT ;
    USE SIGNAL ;
    PORT
      LAYER M5 ;
        RECT 140.2080 129.5160 140.2320 129.6000 ;
    END
  END xf[30]
  PIN xf[31]
    DIRECTION OUTPUT ;
    USE SIGNAL ;
    PORT
      LAYER M3 ;
        RECT 139.6440 129.5620 139.6620 129.6000 ;
    END
  END xf[31]
  PIN xf[32]
    DIRECTION OUTPUT ;
    USE SIGNAL ;
    PORT
      LAYER M5 ;
        RECT 139.0560 129.5160 139.0800 129.6000 ;
    END
  END xf[32]
  PIN xf[33]
    DIRECTION OUTPUT ;
    USE SIGNAL ;
    PORT
      LAYER M3 ;
        RECT 138.5640 129.5620 138.5820 129.6000 ;
    END
  END xf[33]
  PIN xf[34]
    DIRECTION OUTPUT ;
    USE SIGNAL ;
    PORT
      LAYER M5 ;
        RECT 138.0000 129.5160 138.0240 129.6000 ;
    END
  END xf[34]
  PIN xf[35]
    DIRECTION OUTPUT ;
    USE SIGNAL ;
    PORT
      LAYER M3 ;
        RECT 137.4120 129.5620 137.4300 129.6000 ;
    END
  END xf[35]
  PIN xf[36]
    DIRECTION OUTPUT ;
    USE SIGNAL ;
    PORT
      LAYER M5 ;
        RECT 136.8480 129.5160 136.8720 129.6000 ;
    END
  END xf[36]
  PIN xf[37]
    DIRECTION OUTPUT ;
    USE SIGNAL ;
    PORT
      LAYER M3 ;
        RECT 136.3320 129.5620 136.3500 129.6000 ;
    END
  END xf[37]
  PIN xf[38]
    DIRECTION OUTPUT ;
    USE SIGNAL ;
    PORT
      LAYER M5 ;
        RECT 135.7920 129.5160 135.8160 129.6000 ;
    END
  END xf[38]
  PIN xf[39]
    DIRECTION OUTPUT ;
    USE SIGNAL ;
    PORT
      LAYER M3 ;
        RECT 135.2520 129.5620 135.2700 129.6000 ;
    END
  END xf[39]
  PIN xf[3]
    DIRECTION OUTPUT ;
    USE SIGNAL ;
    PORT
      LAYER M3 ;
        RECT 154.9800 129.5620 154.9980 129.6000 ;
    END
  END xf[3]
  PIN xf[40]
    DIRECTION OUTPUT ;
    USE SIGNAL ;
    PORT
      LAYER M5 ;
        RECT 134.6400 129.5160 134.6640 129.6000 ;
    END
  END xf[40]
  PIN xf[41]
    DIRECTION OUTPUT ;
    USE SIGNAL ;
    PORT
      LAYER M3 ;
        RECT 134.1720 129.5620 134.1900 129.6000 ;
    END
  END xf[41]
  PIN xf[42]
    DIRECTION OUTPUT ;
    USE SIGNAL ;
    PORT
      LAYER M5 ;
        RECT 133.5840 129.5160 133.6080 129.6000 ;
    END
  END xf[42]
  PIN xf[43]
    DIRECTION OUTPUT ;
    USE SIGNAL ;
    PORT
      LAYER M3 ;
        RECT 133.0200 129.5620 133.0380 129.6000 ;
    END
  END xf[43]
  PIN xf[44]
    DIRECTION OUTPUT ;
    USE SIGNAL ;
    PORT
      LAYER M5 ;
        RECT 132.5280 129.5160 132.5520 129.6000 ;
    END
  END xf[44]
  PIN xf[45]
    DIRECTION OUTPUT ;
    USE SIGNAL ;
    PORT
      LAYER M3 ;
        RECT 131.9400 129.5620 131.9580 129.6000 ;
    END
  END xf[45]
  PIN xf[46]
    DIRECTION OUTPUT ;
    USE SIGNAL ;
    PORT
      LAYER M5 ;
        RECT 131.3760 129.5160 131.4000 129.6000 ;
    END
  END xf[46]
  PIN xf[47]
    DIRECTION OUTPUT ;
    USE SIGNAL ;
    PORT
      LAYER M3 ;
        RECT 130.8600 129.5620 130.8780 129.6000 ;
    END
  END xf[47]
  PIN xf[48]
    DIRECTION OUTPUT ;
    USE SIGNAL ;
    PORT
      LAYER M5 ;
        RECT 130.3200 129.5160 130.3440 129.6000 ;
    END
  END xf[48]
  PIN xf[49]
    DIRECTION OUTPUT ;
    USE SIGNAL ;
    PORT
      LAYER M3 ;
        RECT 129.7800 129.5620 129.7980 129.6000 ;
    END
  END xf[49]
  PIN xf[4]
    DIRECTION OUTPUT ;
    USE SIGNAL ;
    PORT
      LAYER M5 ;
        RECT 154.4160 129.5160 154.4400 129.6000 ;
    END
  END xf[4]
  PIN xf[50]
    DIRECTION OUTPUT ;
    USE SIGNAL ;
    PORT
      LAYER M5 ;
        RECT 129.1680 129.5160 129.1920 129.6000 ;
    END
  END xf[50]
  PIN xf[51]
    DIRECTION OUTPUT ;
    USE SIGNAL ;
    PORT
      LAYER M3 ;
        RECT 128.6280 129.5620 128.6460 129.6000 ;
    END
  END xf[51]
  PIN xf[52]
    DIRECTION OUTPUT ;
    USE SIGNAL ;
    PORT
      LAYER M5 ;
        RECT 128.1120 129.5160 128.1360 129.6000 ;
    END
  END xf[52]
  PIN xf[53]
    DIRECTION OUTPUT ;
    USE SIGNAL ;
    PORT
      LAYER M3 ;
        RECT 127.5480 129.5620 127.5660 129.6000 ;
    END
  END xf[53]
  PIN xf[54]
    DIRECTION OUTPUT ;
    USE SIGNAL ;
    PORT
      LAYER M5 ;
        RECT 126.9600 129.5160 126.9840 129.6000 ;
    END
  END xf[54]
  PIN xf[55]
    DIRECTION OUTPUT ;
    USE SIGNAL ;
    PORT
      LAYER M3 ;
        RECT 126.4680 129.5620 126.4860 129.6000 ;
    END
  END xf[55]
  PIN xf[56]
    DIRECTION OUTPUT ;
    USE SIGNAL ;
    PORT
      LAYER M5 ;
        RECT 125.9040 129.5160 125.9280 129.6000 ;
    END
  END xf[56]
  PIN xf[57]
    DIRECTION OUTPUT ;
    USE SIGNAL ;
    PORT
      LAYER M3 ;
        RECT 125.3880 129.5620 125.4060 129.6000 ;
    END
  END xf[57]
  PIN xf[58]
    DIRECTION OUTPUT ;
    USE SIGNAL ;
    PORT
      LAYER M5 ;
        RECT 124.7520 129.5160 124.7760 129.6000 ;
    END
  END xf[58]
  PIN xf[59]
    DIRECTION OUTPUT ;
    USE SIGNAL ;
    PORT
      LAYER M3 ;
        RECT 124.2360 129.5620 124.2540 129.6000 ;
    END
  END xf[59]
  PIN xf[5]
    DIRECTION OUTPUT ;
    USE SIGNAL ;
    PORT
      LAYER M3 ;
        RECT 153.9000 129.5620 153.9180 129.6000 ;
    END
  END xf[5]
  PIN xf[60]
    DIRECTION OUTPUT ;
    USE SIGNAL ;
    PORT
      LAYER M5 ;
        RECT 123.6960 129.5160 123.7200 129.6000 ;
    END
  END xf[60]
  PIN xf[61]
    DIRECTION OUTPUT ;
    USE SIGNAL ;
    PORT
      LAYER M3 ;
        RECT 123.1560 129.5620 123.1740 129.6000 ;
    END
  END xf[61]
  PIN xf[62]
    DIRECTION OUTPUT ;
    USE SIGNAL ;
    PORT
      LAYER M5 ;
        RECT 122.6400 129.5160 122.6640 129.6000 ;
    END
  END xf[62]
  PIN xf[63]
    DIRECTION OUTPUT ;
    USE SIGNAL ;
    PORT
      LAYER M3 ;
        RECT 122.0760 129.5620 122.0940 129.6000 ;
    END
  END xf[63]
  PIN xf[64]
    DIRECTION OUTPUT ;
    USE SIGNAL ;
    PORT
      LAYER M5 ;
        RECT 121.4880 129.5160 121.5120 129.6000 ;
    END
  END xf[64]
  PIN xf[65]
    DIRECTION OUTPUT ;
    USE SIGNAL ;
    PORT
      LAYER M3 ;
        RECT 120.9960 129.5620 121.0140 129.6000 ;
    END
  END xf[65]
  PIN xf[66]
    DIRECTION OUTPUT ;
    USE SIGNAL ;
    PORT
      LAYER M5 ;
        RECT 120.4320 129.5160 120.4560 129.6000 ;
    END
  END xf[66]
  PIN xf[67]
    DIRECTION OUTPUT ;
    USE SIGNAL ;
    PORT
      LAYER M3 ;
        RECT 119.8440 129.5620 119.8620 129.6000 ;
    END
  END xf[67]
  PIN xf[68]
    DIRECTION OUTPUT ;
    USE SIGNAL ;
    PORT
      LAYER M5 ;
        RECT 119.2800 129.5160 119.3040 129.6000 ;
    END
  END xf[68]
  PIN xf[69]
    DIRECTION OUTPUT ;
    USE SIGNAL ;
    PORT
      LAYER M3 ;
        RECT 118.7640 129.5620 118.7820 129.6000 ;
    END
  END xf[69]
  PIN xf[6]
    DIRECTION OUTPUT ;
    USE SIGNAL ;
    PORT
      LAYER M5 ;
        RECT 153.3600 129.5160 153.3840 129.6000 ;
    END
  END xf[6]
  PIN xf[70]
    DIRECTION OUTPUT ;
    USE SIGNAL ;
    PORT
      LAYER M5 ;
        RECT 118.2240 129.5160 118.2480 129.6000 ;
    END
  END xf[70]
  PIN xf[71]
    DIRECTION OUTPUT ;
    USE SIGNAL ;
    PORT
      LAYER M3 ;
        RECT 117.6840 129.5620 117.7020 129.6000 ;
    END
  END xf[71]
  PIN xf[72]
    DIRECTION OUTPUT ;
    USE SIGNAL ;
    PORT
      LAYER M5 ;
        RECT 117.0720 129.5160 117.0960 129.6000 ;
    END
  END xf[72]
  PIN xf[73]
    DIRECTION OUTPUT ;
    USE SIGNAL ;
    PORT
      LAYER M3 ;
        RECT 116.6040 129.5620 116.6220 129.6000 ;
    END
  END xf[73]
  PIN xf[74]
    DIRECTION OUTPUT ;
    USE SIGNAL ;
    PORT
      LAYER M5 ;
        RECT 116.0160 129.5160 116.0400 129.6000 ;
    END
  END xf[74]
  PIN xf[75]
    DIRECTION OUTPUT ;
    USE SIGNAL ;
    PORT
      LAYER M3 ;
        RECT 115.4520 129.5620 115.4700 129.6000 ;
    END
  END xf[75]
  PIN xf[76]
    DIRECTION OUTPUT ;
    USE SIGNAL ;
    PORT
      LAYER M5 ;
        RECT 114.9600 129.5160 114.9840 129.6000 ;
    END
  END xf[76]
  PIN xf[77]
    DIRECTION OUTPUT ;
    USE SIGNAL ;
    PORT
      LAYER M3 ;
        RECT 114.3720 129.5620 114.3900 129.6000 ;
    END
  END xf[77]
  PIN xf[78]
    DIRECTION OUTPUT ;
    USE SIGNAL ;
    PORT
      LAYER M5 ;
        RECT 113.8080 129.5160 113.8320 129.6000 ;
    END
  END xf[78]
  PIN xf[79]
    DIRECTION OUTPUT ;
    USE SIGNAL ;
    PORT
      LAYER M3 ;
        RECT 113.2920 129.5620 113.3100 129.6000 ;
    END
  END xf[79]
  PIN xf[7]
    DIRECTION OUTPUT ;
    USE SIGNAL ;
    PORT
      LAYER M3 ;
        RECT 152.8200 129.5620 152.8380 129.6000 ;
    END
  END xf[7]
  PIN xf[80]
    DIRECTION OUTPUT ;
    USE SIGNAL ;
    PORT
      LAYER M5 ;
        RECT 112.7520 129.5160 112.7760 129.6000 ;
    END
  END xf[80]
  PIN xf[81]
    DIRECTION OUTPUT ;
    USE SIGNAL ;
    PORT
      LAYER M3 ;
        RECT 112.2120 129.5620 112.2300 129.6000 ;
    END
  END xf[81]
  PIN xf[82]
    DIRECTION OUTPUT ;
    USE SIGNAL ;
    PORT
      LAYER M5 ;
        RECT 111.6000 129.5160 111.6240 129.6000 ;
    END
  END xf[82]
  PIN xf[83]
    DIRECTION OUTPUT ;
    USE SIGNAL ;
    PORT
      LAYER M3 ;
        RECT 111.0600 129.5620 111.0780 129.6000 ;
    END
  END xf[83]
  PIN xf[84]
    DIRECTION OUTPUT ;
    USE SIGNAL ;
    PORT
      LAYER M5 ;
        RECT 110.5440 129.5160 110.5680 129.6000 ;
    END
  END xf[84]
  PIN xf[85]
    DIRECTION OUTPUT ;
    USE SIGNAL ;
    PORT
      LAYER M3 ;
        RECT 109.9800 129.5620 109.9980 129.6000 ;
    END
  END xf[85]
  PIN xf[86]
    DIRECTION OUTPUT ;
    USE SIGNAL ;
    PORT
      LAYER M5 ;
        RECT 109.3920 129.5160 109.4160 129.6000 ;
    END
  END xf[86]
  PIN xf[87]
    DIRECTION OUTPUT ;
    USE SIGNAL ;
    PORT
      LAYER M3 ;
        RECT 108.9000 129.5620 108.9180 129.6000 ;
    END
  END xf[87]
  PIN xf[88]
    DIRECTION OUTPUT ;
    USE SIGNAL ;
    PORT
      LAYER M5 ;
        RECT 108.3360 129.5160 108.3600 129.6000 ;
    END
  END xf[88]
  PIN xf[89]
    DIRECTION OUTPUT ;
    USE SIGNAL ;
    PORT
      LAYER M3 ;
        RECT 107.8200 129.5620 107.8380 129.6000 ;
    END
  END xf[89]
  PIN xf[8]
    DIRECTION OUTPUT ;
    USE SIGNAL ;
    PORT
      LAYER M5 ;
        RECT 152.2080 129.5160 152.2320 129.6000 ;
    END
  END xf[8]
  PIN xf[90]
    DIRECTION OUTPUT ;
    USE SIGNAL ;
    PORT
      LAYER M5 ;
        RECT 107.1840 129.5160 107.2080 129.6000 ;
    END
  END xf[90]
  PIN xf[91]
    DIRECTION OUTPUT ;
    USE SIGNAL ;
    PORT
      LAYER M3 ;
        RECT 106.6680 129.5620 106.6860 129.6000 ;
    END
  END xf[91]
  PIN xf[92]
    DIRECTION OUTPUT ;
    USE SIGNAL ;
    PORT
      LAYER M5 ;
        RECT 106.1280 129.5160 106.1520 129.6000 ;
    END
  END xf[92]
  PIN xf[93]
    DIRECTION OUTPUT ;
    USE SIGNAL ;
    PORT
      LAYER M3 ;
        RECT 105.5880 129.5620 105.6060 129.6000 ;
    END
  END xf[93]
  PIN xf[94]
    DIRECTION OUTPUT ;
    USE SIGNAL ;
    PORT
      LAYER M5 ;
        RECT 105.0720 129.5160 105.0960 129.6000 ;
    END
  END xf[94]
  PIN xf[95]
    DIRECTION OUTPUT ;
    USE SIGNAL ;
    PORT
      LAYER M3 ;
        RECT 104.5080 129.5620 104.5260 129.6000 ;
    END
  END xf[95]
  PIN xf[96]
    DIRECTION OUTPUT ;
    USE SIGNAL ;
    PORT
      LAYER M5 ;
        RECT 103.9200 129.5160 103.9440 129.6000 ;
    END
  END xf[96]
  PIN xf[97]
    DIRECTION OUTPUT ;
    USE SIGNAL ;
    PORT
      LAYER M3 ;
        RECT 103.4280 129.5620 103.4460 129.6000 ;
    END
  END xf[97]
  PIN xf[98]
    DIRECTION OUTPUT ;
    USE SIGNAL ;
    PORT
      LAYER M5 ;
        RECT 102.8640 129.5160 102.8880 129.6000 ;
    END
  END xf[98]
  PIN xf[99]
    DIRECTION OUTPUT ;
    USE SIGNAL ;
    PORT
      LAYER M3 ;
        RECT 102.2760 129.5620 102.2940 129.6000 ;
    END
  END xf[99]
  PIN xf[9]
    DIRECTION OUTPUT ;
    USE SIGNAL ;
    PORT
      LAYER M3 ;
        RECT 151.7400 129.5620 151.7580 129.6000 ;
    END
  END xf[9]
  PIN xf_s
    DIRECTION OUTPUT ;
    USE SIGNAL ;
    PORT
      LAYER M3 ;
        RECT 157.2120 129.5620 157.2300 129.6000 ;
    END
  END xf_s
  PIN xf_v
    DIRECTION OUTPUT ;
    USE SIGNAL ;
    PORT
      LAYER M5 ;
        RECT 157.7760 129.5160 157.8000 129.6000 ;
    END
  END xf_v
  PIN y[48]
    DIRECTION INPUT ;
    USE SIGNAL ;
    PORT
      LAYER M4 ;
        RECT 172.7160 111.0720 172.8000 111.0960 ;
    END
  END y[48]
  PIN y[49]
    DIRECTION INPUT ;
    USE SIGNAL ;
    PORT
      LAYER M4 ;
        RECT 172.7160 111.9360 172.8000 111.9600 ;
    END
  END y[49]
  PIN y[50]
    DIRECTION INPUT ;
    USE SIGNAL ;
    PORT
      LAYER M4 ;
        RECT 172.7160 112.8960 172.8000 112.9200 ;
    END
  END y[50]
  PIN y[51]
    DIRECTION INPUT ;
    USE SIGNAL ;
    PORT
      LAYER M4 ;
        RECT 172.7160 113.8560 172.8000 113.8800 ;
    END
  END y[51]
  PIN y[52]
    DIRECTION INPUT ;
    USE SIGNAL ;
    PORT
      LAYER M4 ;
        RECT 172.7160 114.7200 172.8000 114.7440 ;
    END
  END y[52]
  PIN y[53]
    DIRECTION INPUT ;
    USE SIGNAL ;
    PORT
      LAYER M4 ;
        RECT 172.7160 115.6800 172.8000 115.7040 ;
    END
  END y[53]
  PIN y[54]
    DIRECTION INPUT ;
    USE SIGNAL ;
    PORT
      LAYER M4 ;
        RECT 172.7160 116.5440 172.8000 116.5680 ;
    END
  END y[54]
  PIN y[55]
    DIRECTION INPUT ;
    USE SIGNAL ;
    PORT
      LAYER M4 ;
        RECT 172.7160 117.5040 172.8000 117.5280 ;
    END
  END y[55]
  PIN y[56]
    DIRECTION INPUT ;
    USE SIGNAL ;
    PORT
      LAYER M4 ;
        RECT 172.7160 118.3680 172.8000 118.3920 ;
    END
  END y[56]
  PIN y[57]
    DIRECTION INPUT ;
    USE SIGNAL ;
    PORT
      LAYER M4 ;
        RECT 172.7160 119.3280 172.8000 119.3520 ;
    END
  END y[57]
  PIN y[58]
    DIRECTION INPUT ;
    USE SIGNAL ;
    PORT
      LAYER M4 ;
        RECT 172.7160 120.1920 172.8000 120.2160 ;
    END
  END y[58]
  PIN y[59]
    DIRECTION INPUT ;
    USE SIGNAL ;
    PORT
      LAYER M4 ;
        RECT 172.7160 121.1520 172.8000 121.1760 ;
    END
  END y[59]
  PIN y[60]
    DIRECTION INPUT ;
    USE SIGNAL ;
    PORT
      LAYER M4 ;
        RECT 172.7160 122.0160 172.8000 122.0400 ;
    END
  END y[60]
  PIN y[61]
    DIRECTION INPUT ;
    USE SIGNAL ;
    PORT
      LAYER M4 ;
        RECT 172.7160 122.9760 172.8000 123.0000 ;
    END
  END y[61]
  PIN y[62]
    DIRECTION INPUT ;
    USE SIGNAL ;
    PORT
      LAYER M4 ;
        RECT 172.7160 123.9360 172.8000 123.9600 ;
    END
  END y[62]
  PIN y[63]
    DIRECTION INPUT ;
    USE SIGNAL ;
    PORT
      LAYER M4 ;
        RECT 172.7160 124.8000 172.8000 124.8240 ;
    END
  END y[63]
  PIN y[0]
    DIRECTION INPUT ;
    USE SIGNAL ;
    PORT
      LAYER M4 ;
        RECT 172.7160 23.1360 172.8000 23.1600 ;
    END
  END y[0]
  PIN y[1]
    DIRECTION INPUT ;
    USE SIGNAL ;
    PORT
      LAYER M4 ;
        RECT 172.7160 24.0000 172.8000 24.0240 ;
    END
  END y[1]
  PIN y[2]
    DIRECTION INPUT ;
    USE SIGNAL ;
    PORT
      LAYER M4 ;
        RECT 172.7160 24.9600 172.8000 24.9840 ;
    END
  END y[2]
  PIN y[3]
    DIRECTION INPUT ;
    USE SIGNAL ;
    PORT
      LAYER M4 ;
        RECT 172.7160 25.8240 172.8000 25.8480 ;
    END
  END y[3]
  PIN y[4]
    DIRECTION INPUT ;
    USE SIGNAL ;
    PORT
      LAYER M4 ;
        RECT 172.7160 26.7840 172.8000 26.8080 ;
    END
  END y[4]
  PIN y[5]
    DIRECTION INPUT ;
    USE SIGNAL ;
    PORT
      LAYER M4 ;
        RECT 172.7160 27.6480 172.8000 27.6720 ;
    END
  END y[5]
  PIN y[6]
    DIRECTION INPUT ;
    USE SIGNAL ;
    PORT
      LAYER M4 ;
        RECT 172.7160 28.6080 172.8000 28.6320 ;
    END
  END y[6]
  PIN y[7]
    DIRECTION INPUT ;
    USE SIGNAL ;
    PORT
      LAYER M4 ;
        RECT 172.7160 29.4720 172.8000 29.4960 ;
    END
  END y[7]
  PIN y[8]
    DIRECTION INPUT ;
    USE SIGNAL ;
    PORT
      LAYER M4 ;
        RECT 172.7160 30.4320 172.8000 30.4560 ;
    END
  END y[8]
  PIN y[9]
    DIRECTION INPUT ;
    USE SIGNAL ;
    PORT
      LAYER M4 ;
        RECT 172.7160 31.2960 172.8000 31.3200 ;
    END
  END y[9]
  PIN y[10]
    DIRECTION INPUT ;
    USE SIGNAL ;
    PORT
      LAYER M4 ;
        RECT 172.7160 32.2560 172.8000 32.2800 ;
    END
  END y[10]
  PIN y[11]
    DIRECTION INPUT ;
    USE SIGNAL ;
    PORT
      LAYER M4 ;
        RECT 172.7160 33.2160 172.8000 33.2400 ;
    END
  END y[11]
  PIN y[12]
    DIRECTION INPUT ;
    USE SIGNAL ;
    PORT
      LAYER M4 ;
        RECT 172.7160 34.0800 172.8000 34.1040 ;
    END
  END y[12]
  PIN y[13]
    DIRECTION INPUT ;
    USE SIGNAL ;
    PORT
      LAYER M4 ;
        RECT 172.7160 35.0400 172.8000 35.0640 ;
    END
  END y[13]
  PIN y[14]
    DIRECTION INPUT ;
    USE SIGNAL ;
    PORT
      LAYER M4 ;
        RECT 172.7160 35.9040 172.8000 35.9280 ;
    END
  END y[14]
  PIN y[15]
    DIRECTION INPUT ;
    USE SIGNAL ;
    PORT
      LAYER M4 ;
        RECT 172.7160 36.8640 172.8000 36.8880 ;
    END
  END y[15]
  PIN y[16]
    DIRECTION INPUT ;
    USE SIGNAL ;
    PORT
      LAYER M4 ;
        RECT 172.7160 52.4160 172.8000 52.4400 ;
    END
  END y[16]
  PIN y[17]
    DIRECTION INPUT ;
    USE SIGNAL ;
    PORT
      LAYER M4 ;
        RECT 172.7160 53.3760 172.8000 53.4000 ;
    END
  END y[17]
  PIN y[18]
    DIRECTION INPUT ;
    USE SIGNAL ;
    PORT
      LAYER M4 ;
        RECT 172.7160 54.2400 172.8000 54.2640 ;
    END
  END y[18]
  PIN y[19]
    DIRECTION INPUT ;
    USE SIGNAL ;
    PORT
      LAYER M4 ;
        RECT 172.7160 55.2000 172.8000 55.2240 ;
    END
  END y[19]
  PIN y[20]
    DIRECTION INPUT ;
    USE SIGNAL ;
    PORT
      LAYER M4 ;
        RECT 172.7160 56.0640 172.8000 56.0880 ;
    END
  END y[20]
  PIN y[21]
    DIRECTION INPUT ;
    USE SIGNAL ;
    PORT
      LAYER M4 ;
        RECT 172.7160 57.0240 172.8000 57.0480 ;
    END
  END y[21]
  PIN y[22]
    DIRECTION INPUT ;
    USE SIGNAL ;
    PORT
      LAYER M4 ;
        RECT 172.7160 57.8880 172.8000 57.9120 ;
    END
  END y[22]
  PIN y[23]
    DIRECTION INPUT ;
    USE SIGNAL ;
    PORT
      LAYER M4 ;
        RECT 172.7160 58.8480 172.8000 58.8720 ;
    END
  END y[23]
  PIN y[24]
    DIRECTION INPUT ;
    USE SIGNAL ;
    PORT
      LAYER M4 ;
        RECT 172.7160 59.7120 172.8000 59.7360 ;
    END
  END y[24]
  PIN y[25]
    DIRECTION INPUT ;
    USE SIGNAL ;
    PORT
      LAYER M4 ;
        RECT 172.7160 60.6720 172.8000 60.6960 ;
    END
  END y[25]
  PIN y[26]
    DIRECTION INPUT ;
    USE SIGNAL ;
    PORT
      LAYER M4 ;
        RECT 172.7160 61.5360 172.8000 61.5600 ;
    END
  END y[26]
  PIN y[27]
    DIRECTION INPUT ;
    USE SIGNAL ;
    PORT
      LAYER M4 ;
        RECT 172.7160 62.4960 172.8000 62.5200 ;
    END
  END y[27]
  PIN y[28]
    DIRECTION INPUT ;
    USE SIGNAL ;
    PORT
      LAYER M4 ;
        RECT 172.7160 63.4560 172.8000 63.4800 ;
    END
  END y[28]
  PIN y[29]
    DIRECTION INPUT ;
    USE SIGNAL ;
    PORT
      LAYER M4 ;
        RECT 172.7160 64.3200 172.8000 64.3440 ;
    END
  END y[29]
  PIN y[30]
    DIRECTION INPUT ;
    USE SIGNAL ;
    PORT
      LAYER M4 ;
        RECT 172.7160 65.2800 172.8000 65.3040 ;
    END
  END y[30]
  PIN y[31]
    DIRECTION INPUT ;
    USE SIGNAL ;
    PORT
      LAYER M4 ;
        RECT 172.7160 66.1440 172.8000 66.1680 ;
    END
  END y[31]
  PIN y[32]
    DIRECTION INPUT ;
    USE SIGNAL ;
    PORT
      LAYER M4 ;
        RECT 172.7160 81.6960 172.8000 81.7200 ;
    END
  END y[32]
  PIN y[33]
    DIRECTION INPUT ;
    USE SIGNAL ;
    PORT
      LAYER M4 ;
        RECT 172.7160 82.6560 172.8000 82.6800 ;
    END
  END y[33]
  PIN y[34]
    DIRECTION INPUT ;
    USE SIGNAL ;
    PORT
      LAYER M4 ;
        RECT 172.7160 83.6160 172.8000 83.6400 ;
    END
  END y[34]
  PIN y[35]
    DIRECTION INPUT ;
    USE SIGNAL ;
    PORT
      LAYER M4 ;
        RECT 172.7160 84.4800 172.8000 84.5040 ;
    END
  END y[35]
  PIN y[36]
    DIRECTION INPUT ;
    USE SIGNAL ;
    PORT
      LAYER M4 ;
        RECT 172.7160 85.4400 172.8000 85.4640 ;
    END
  END y[36]
  PIN y[37]
    DIRECTION INPUT ;
    USE SIGNAL ;
    PORT
      LAYER M4 ;
        RECT 172.7160 86.3040 172.8000 86.3280 ;
    END
  END y[37]
  PIN y[38]
    DIRECTION INPUT ;
    USE SIGNAL ;
    PORT
      LAYER M4 ;
        RECT 172.7160 87.2640 172.8000 87.2880 ;
    END
  END y[38]
  PIN y[39]
    DIRECTION INPUT ;
    USE SIGNAL ;
    PORT
      LAYER M4 ;
        RECT 172.7160 88.1280 172.8000 88.1520 ;
    END
  END y[39]
  PIN y[40]
    DIRECTION INPUT ;
    USE SIGNAL ;
    PORT
      LAYER M4 ;
        RECT 172.7160 89.0880 172.8000 89.1120 ;
    END
  END y[40]
  PIN y[41]
    DIRECTION INPUT ;
    USE SIGNAL ;
    PORT
      LAYER M4 ;
        RECT 172.7160 89.9520 172.8000 89.9760 ;
    END
  END y[41]
  PIN y[42]
    DIRECTION INPUT ;
    USE SIGNAL ;
    PORT
      LAYER M4 ;
        RECT 172.7160 90.9120 172.8000 90.9360 ;
    END
  END y[42]
  PIN y[43]
    DIRECTION INPUT ;
    USE SIGNAL ;
    PORT
      LAYER M4 ;
        RECT 172.7160 91.7760 172.8000 91.8000 ;
    END
  END y[43]
  PIN y[44]
    DIRECTION INPUT ;
    USE SIGNAL ;
    PORT
      LAYER M4 ;
        RECT 172.7160 92.7360 172.8000 92.7600 ;
    END
  END y[44]
  PIN y[45]
    DIRECTION INPUT ;
    USE SIGNAL ;
    PORT
      LAYER M4 ;
        RECT 172.7160 93.6960 172.8000 93.7200 ;
    END
  END y[45]
  PIN y[46]
    DIRECTION INPUT ;
    USE SIGNAL ;
    PORT
      LAYER M4 ;
        RECT 172.7160 94.5600 172.8000 94.5840 ;
    END
  END y[46]
  PIN y[47]
    DIRECTION INPUT ;
    USE SIGNAL ;
    PORT
      LAYER M4 ;
        RECT 172.7160 95.5200 172.8000 95.5440 ;
    END
  END y[47]
  PIN y_i[0]
    DIRECTION INPUT ;
    USE SIGNAL ;
    PORT
      LAYER M4 ;
        RECT 172.7160 5.6640 172.8000 5.6880 ;
    END
  END y_i[0]
  PIN y_i[1]
    DIRECTION INPUT ;
    USE SIGNAL ;
    PORT
      LAYER M4 ;
        RECT 172.7160 6.6240 172.8000 6.6480 ;
    END
  END y_i[1]
  PIN y_i[2]
    DIRECTION INPUT ;
    USE SIGNAL ;
    PORT
      LAYER M4 ;
        RECT 172.7160 7.4880 172.8000 7.5120 ;
    END
  END y_i[2]
  PIN y_v
    DIRECTION INPUT ;
    USE SIGNAL ;
    PORT
      LAYER M4 ;
        RECT 172.7160 4.8000 172.8000 4.8240 ;
    END
  END y_v
  OBS
    LAYER M1 ;
      RECT 0.5 0.5 172.300 129.100 ;
    LAYER M2 ;
      RECT 0.5 0.5 172.300 129.100 ;
    LAYER M3 ;
      RECT 0.5 0.5 172.300 129.100 ;
    LAYER M4 ;
      RECT 0.5 0.5 172.300 129.100 ;
    LAYER M5 ;
      RECT 0.5 0.5 172.300 129.100 ;
  END
END ot_s81sl_vq
END LIBRARY
